VERSION 5.7 ;
BUSBITCHARS "[]" ;
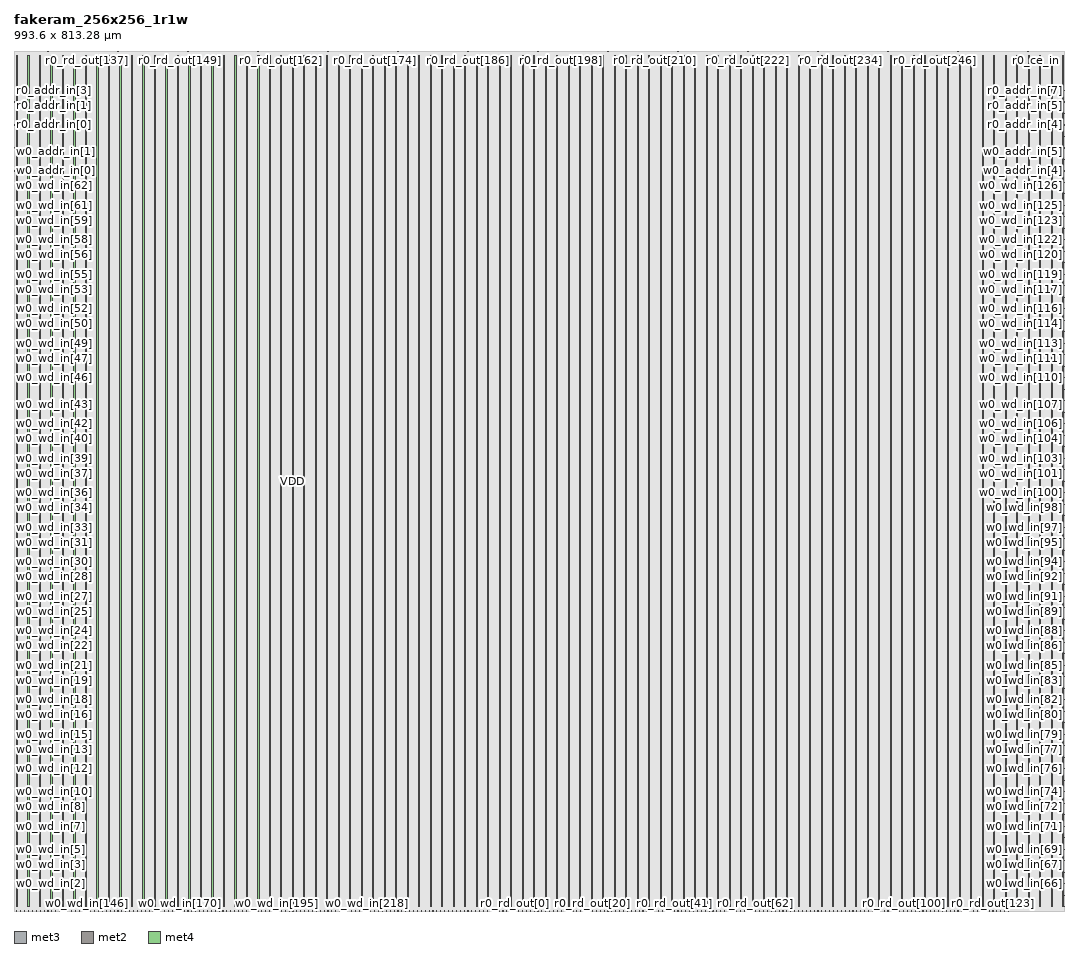
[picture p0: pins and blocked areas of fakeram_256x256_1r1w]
MACRO fakeram_256x256_1r1w
  FOREIGN fakeram_256x256_1r1w 0 0 ;
  SYMMETRY X Y R90 ;
  SIZE 993.600 BY 813.280 ;
  CLASS BLOCK ;
  PIN w0_wd_in[0]
    DIRECTION INPUT ;
    USE SIGNAL ;
    SHAPE ABUTMENT ;
    PORT
      LAYER met3 ;
      RECT 0.000 3.930 0.900 4.230 ;
    END
  END w0_wd_in[0]
  PIN w0_wd_in[1]
    DIRECTION INPUT ;
    USE SIGNAL ;
    SHAPE ABUTMENT ;
    PORT
      LAYER met3 ;
      RECT 0.000 14.810 0.900 15.110 ;
    END
  END w0_wd_in[1]
  PIN w0_wd_in[2]
    DIRECTION INPUT ;
    USE SIGNAL ;
    SHAPE ABUTMENT ;
    PORT
      LAYER met3 ;
      RECT 0.000 25.690 0.900 25.990 ;
    END
  END w0_wd_in[2]
  PIN w0_wd_in[3]
    DIRECTION INPUT ;
    USE SIGNAL ;
    SHAPE ABUTMENT ;
    PORT
      LAYER met3 ;
      RECT 0.000 36.570 0.900 36.870 ;
    END
  END w0_wd_in[3]
  PIN w0_wd_in[4]
    DIRECTION INPUT ;
    USE SIGNAL ;
    SHAPE ABUTMENT ;
    PORT
      LAYER met3 ;
      RECT 0.000 47.450 0.900 47.750 ;
    END
  END w0_wd_in[4]
  PIN w0_wd_in[5]
    DIRECTION INPUT ;
    USE SIGNAL ;
    SHAPE ABUTMENT ;
    PORT
      LAYER met3 ;
      RECT 0.000 58.330 0.900 58.630 ;
    END
  END w0_wd_in[5]
  PIN w0_wd_in[6]
    DIRECTION INPUT ;
    USE SIGNAL ;
    SHAPE ABUTMENT ;
    PORT
      LAYER met3 ;
      RECT 0.000 69.210 0.900 69.510 ;
    END
  END w0_wd_in[6]
  PIN w0_wd_in[7]
    DIRECTION INPUT ;
    USE SIGNAL ;
    SHAPE ABUTMENT ;
    PORT
      LAYER met3 ;
      RECT 0.000 80.090 0.900 80.390 ;
    END
  END w0_wd_in[7]
  PIN w0_wd_in[8]
    DIRECTION INPUT ;
    USE SIGNAL ;
    SHAPE ABUTMENT ;
    PORT
      LAYER met3 ;
      RECT 0.000 90.970 0.900 91.270 ;
    END
  END w0_wd_in[8]
  PIN w0_wd_in[9]
    DIRECTION INPUT ;
    USE SIGNAL ;
    SHAPE ABUTMENT ;
    PORT
      LAYER met3 ;
      RECT 0.000 101.850 0.900 102.150 ;
    END
  END w0_wd_in[9]
  PIN w0_wd_in[10]
    DIRECTION INPUT ;
    USE SIGNAL ;
    SHAPE ABUTMENT ;
    PORT
      LAYER met3 ;
      RECT 0.000 112.730 0.900 113.030 ;
    END
  END w0_wd_in[10]
  PIN w0_wd_in[11]
    DIRECTION INPUT ;
    USE SIGNAL ;
    SHAPE ABUTMENT ;
    PORT
      LAYER met3 ;
      RECT 0.000 123.610 0.900 123.910 ;
    END
  END w0_wd_in[11]
  PIN w0_wd_in[12]
    DIRECTION INPUT ;
    USE SIGNAL ;
    SHAPE ABUTMENT ;
    PORT
      LAYER met3 ;
      RECT 0.000 134.490 0.900 134.790 ;
    END
  END w0_wd_in[12]
  PIN w0_wd_in[13]
    DIRECTION INPUT ;
    USE SIGNAL ;
    SHAPE ABUTMENT ;
    PORT
      LAYER met3 ;
      RECT 0.000 145.370 0.900 145.670 ;
    END
  END w0_wd_in[13]
  PIN w0_wd_in[14]
    DIRECTION INPUT ;
    USE SIGNAL ;
    SHAPE ABUTMENT ;
    PORT
      LAYER met3 ;
      RECT 0.000 156.250 0.900 156.550 ;
    END
  END w0_wd_in[14]
  PIN w0_wd_in[15]
    DIRECTION INPUT ;
    USE SIGNAL ;
    SHAPE ABUTMENT ;
    PORT
      LAYER met3 ;
      RECT 0.000 167.130 0.900 167.430 ;
    END
  END w0_wd_in[15]
  PIN w0_wd_in[16]
    DIRECTION INPUT ;
    USE SIGNAL ;
    SHAPE ABUTMENT ;
    PORT
      LAYER met3 ;
      RECT 0.000 178.010 0.900 178.310 ;
    END
  END w0_wd_in[16]
  PIN w0_wd_in[17]
    DIRECTION INPUT ;
    USE SIGNAL ;
    SHAPE ABUTMENT ;
    PORT
      LAYER met3 ;
      RECT 0.000 188.890 0.900 189.190 ;
    END
  END w0_wd_in[17]
  PIN w0_wd_in[18]
    DIRECTION INPUT ;
    USE SIGNAL ;
    SHAPE ABUTMENT ;
    PORT
      LAYER met3 ;
      RECT 0.000 199.770 0.900 200.070 ;
    END
  END w0_wd_in[18]
  PIN w0_wd_in[19]
    DIRECTION INPUT ;
    USE SIGNAL ;
    SHAPE ABUTMENT ;
    PORT
      LAYER met3 ;
      RECT 0.000 210.650 0.900 210.950 ;
    END
  END w0_wd_in[19]
  PIN w0_wd_in[20]
    DIRECTION INPUT ;
    USE SIGNAL ;
    SHAPE ABUTMENT ;
    PORT
      LAYER met3 ;
      RECT 0.000 221.530 0.900 221.830 ;
    END
  END w0_wd_in[20]
  PIN w0_wd_in[21]
    DIRECTION INPUT ;
    USE SIGNAL ;
    SHAPE ABUTMENT ;
    PORT
      LAYER met3 ;
      RECT 0.000 232.410 0.900 232.710 ;
    END
  END w0_wd_in[21]
  PIN w0_wd_in[22]
    DIRECTION INPUT ;
    USE SIGNAL ;
    SHAPE ABUTMENT ;
    PORT
      LAYER met3 ;
      RECT 0.000 243.290 0.900 243.590 ;
    END
  END w0_wd_in[22]
  PIN w0_wd_in[23]
    DIRECTION INPUT ;
    USE SIGNAL ;
    SHAPE ABUTMENT ;
    PORT
      LAYER met3 ;
      RECT 0.000 254.170 0.900 254.470 ;
    END
  END w0_wd_in[23]
  PIN w0_wd_in[24]
    DIRECTION INPUT ;
    USE SIGNAL ;
    SHAPE ABUTMENT ;
    PORT
      LAYER met3 ;
      RECT 0.000 265.050 0.900 265.350 ;
    END
  END w0_wd_in[24]
  PIN w0_wd_in[25]
    DIRECTION INPUT ;
    USE SIGNAL ;
    SHAPE ABUTMENT ;
    PORT
      LAYER met3 ;
      RECT 0.000 275.930 0.900 276.230 ;
    END
  END w0_wd_in[25]
  PIN w0_wd_in[26]
    DIRECTION INPUT ;
    USE SIGNAL ;
    SHAPE ABUTMENT ;
    PORT
      LAYER met3 ;
      RECT 0.000 286.810 0.900 287.110 ;
    END
  END w0_wd_in[26]
  PIN w0_wd_in[27]
    DIRECTION INPUT ;
    USE SIGNAL ;
    SHAPE ABUTMENT ;
    PORT
      LAYER met3 ;
      RECT 0.000 297.690 0.900 297.990 ;
    END
  END w0_wd_in[27]
  PIN w0_wd_in[28]
    DIRECTION INPUT ;
    USE SIGNAL ;
    SHAPE ABUTMENT ;
    PORT
      LAYER met3 ;
      RECT 0.000 308.570 0.900 308.870 ;
    END
  END w0_wd_in[28]
  PIN w0_wd_in[29]
    DIRECTION INPUT ;
    USE SIGNAL ;
    SHAPE ABUTMENT ;
    PORT
      LAYER met3 ;
      RECT 0.000 319.450 0.900 319.750 ;
    END
  END w0_wd_in[29]
  PIN w0_wd_in[30]
    DIRECTION INPUT ;
    USE SIGNAL ;
    SHAPE ABUTMENT ;
    PORT
      LAYER met3 ;
      RECT 0.000 330.330 0.900 330.630 ;
    END
  END w0_wd_in[30]
  PIN w0_wd_in[31]
    DIRECTION INPUT ;
    USE SIGNAL ;
    SHAPE ABUTMENT ;
    PORT
      LAYER met3 ;
      RECT 0.000 341.210 0.900 341.510 ;
    END
  END w0_wd_in[31]
  PIN w0_wd_in[32]
    DIRECTION INPUT ;
    USE SIGNAL ;
    SHAPE ABUTMENT ;
    PORT
      LAYER met3 ;
      RECT 0.000 352.090 0.900 352.390 ;
    END
  END w0_wd_in[32]
  PIN w0_wd_in[33]
    DIRECTION INPUT ;
    USE SIGNAL ;
    SHAPE ABUTMENT ;
    PORT
      LAYER met3 ;
      RECT 0.000 362.970 0.900 363.270 ;
    END
  END w0_wd_in[33]
  PIN w0_wd_in[34]
    DIRECTION INPUT ;
    USE SIGNAL ;
    SHAPE ABUTMENT ;
    PORT
      LAYER met3 ;
      RECT 0.000 373.850 0.900 374.150 ;
    END
  END w0_wd_in[34]
  PIN w0_wd_in[35]
    DIRECTION INPUT ;
    USE SIGNAL ;
    SHAPE ABUTMENT ;
    PORT
      LAYER met3 ;
      RECT 0.000 384.730 0.900 385.030 ;
    END
  END w0_wd_in[35]
  PIN w0_wd_in[36]
    DIRECTION INPUT ;
    USE SIGNAL ;
    SHAPE ABUTMENT ;
    PORT
      LAYER met3 ;
      RECT 0.000 395.610 0.900 395.910 ;
    END
  END w0_wd_in[36]
  PIN w0_wd_in[37]
    DIRECTION INPUT ;
    USE SIGNAL ;
    SHAPE ABUTMENT ;
    PORT
      LAYER met3 ;
      RECT 0.000 406.490 0.900 406.790 ;
    END
  END w0_wd_in[37]
  PIN w0_wd_in[38]
    DIRECTION INPUT ;
    USE SIGNAL ;
    SHAPE ABUTMENT ;
    PORT
      LAYER met3 ;
      RECT 0.000 417.370 0.900 417.670 ;
    END
  END w0_wd_in[38]
  PIN w0_wd_in[39]
    DIRECTION INPUT ;
    USE SIGNAL ;
    SHAPE ABUTMENT ;
    PORT
      LAYER met3 ;
      RECT 0.000 428.250 0.900 428.550 ;
    END
  END w0_wd_in[39]
  PIN w0_wd_in[40]
    DIRECTION INPUT ;
    USE SIGNAL ;
    SHAPE ABUTMENT ;
    PORT
      LAYER met3 ;
      RECT 0.000 439.130 0.900 439.430 ;
    END
  END w0_wd_in[40]
  PIN w0_wd_in[41]
    DIRECTION INPUT ;
    USE SIGNAL ;
    SHAPE ABUTMENT ;
    PORT
      LAYER met3 ;
      RECT 0.000 450.010 0.900 450.310 ;
    END
  END w0_wd_in[41]
  PIN w0_wd_in[42]
    DIRECTION INPUT ;
    USE SIGNAL ;
    SHAPE ABUTMENT ;
    PORT
      LAYER met3 ;
      RECT 0.000 460.890 0.900 461.190 ;
    END
  END w0_wd_in[42]
  PIN w0_wd_in[43]
    DIRECTION INPUT ;
    USE SIGNAL ;
    SHAPE ABUTMENT ;
    PORT
      LAYER met3 ;
      RECT 0.000 471.770 0.900 472.070 ;
    END
  END w0_wd_in[43]
  PIN w0_wd_in[44]
    DIRECTION INPUT ;
    USE SIGNAL ;
    SHAPE ABUTMENT ;
    PORT
      LAYER met3 ;
      RECT 0.000 482.650 0.900 482.950 ;
    END
  END w0_wd_in[44]
  PIN w0_wd_in[45]
    DIRECTION INPUT ;
    USE SIGNAL ;
    SHAPE ABUTMENT ;
    PORT
      LAYER met3 ;
      RECT 0.000 493.530 0.900 493.830 ;
    END
  END w0_wd_in[45]
  PIN w0_wd_in[46]
    DIRECTION INPUT ;
    USE SIGNAL ;
    SHAPE ABUTMENT ;
    PORT
      LAYER met3 ;
      RECT 0.000 504.410 0.900 504.710 ;
    END
  END w0_wd_in[46]
  PIN w0_wd_in[47]
    DIRECTION INPUT ;
    USE SIGNAL ;
    SHAPE ABUTMENT ;
    PORT
      LAYER met3 ;
      RECT 0.000 515.290 0.900 515.590 ;
    END
  END w0_wd_in[47]
  PIN w0_wd_in[48]
    DIRECTION INPUT ;
    USE SIGNAL ;
    SHAPE ABUTMENT ;
    PORT
      LAYER met3 ;
      RECT 0.000 526.170 0.900 526.470 ;
    END
  END w0_wd_in[48]
  PIN w0_wd_in[49]
    DIRECTION INPUT ;
    USE SIGNAL ;
    SHAPE ABUTMENT ;
    PORT
      LAYER met3 ;
      RECT 0.000 537.050 0.900 537.350 ;
    END
  END w0_wd_in[49]
  PIN w0_wd_in[50]
    DIRECTION INPUT ;
    USE SIGNAL ;
    SHAPE ABUTMENT ;
    PORT
      LAYER met3 ;
      RECT 0.000 547.930 0.900 548.230 ;
    END
  END w0_wd_in[50]
  PIN w0_wd_in[51]
    DIRECTION INPUT ;
    USE SIGNAL ;
    SHAPE ABUTMENT ;
    PORT
      LAYER met3 ;
      RECT 0.000 558.810 0.900 559.110 ;
    END
  END w0_wd_in[51]
  PIN w0_wd_in[52]
    DIRECTION INPUT ;
    USE SIGNAL ;
    SHAPE ABUTMENT ;
    PORT
      LAYER met3 ;
      RECT 0.000 569.690 0.900 569.990 ;
    END
  END w0_wd_in[52]
  PIN w0_wd_in[53]
    DIRECTION INPUT ;
    USE SIGNAL ;
    SHAPE ABUTMENT ;
    PORT
      LAYER met3 ;
      RECT 0.000 580.570 0.900 580.870 ;
    END
  END w0_wd_in[53]
  PIN w0_wd_in[54]
    DIRECTION INPUT ;
    USE SIGNAL ;
    SHAPE ABUTMENT ;
    PORT
      LAYER met3 ;
      RECT 0.000 591.450 0.900 591.750 ;
    END
  END w0_wd_in[54]
  PIN w0_wd_in[55]
    DIRECTION INPUT ;
    USE SIGNAL ;
    SHAPE ABUTMENT ;
    PORT
      LAYER met3 ;
      RECT 0.000 602.330 0.900 602.630 ;
    END
  END w0_wd_in[55]
  PIN w0_wd_in[56]
    DIRECTION INPUT ;
    USE SIGNAL ;
    SHAPE ABUTMENT ;
    PORT
      LAYER met3 ;
      RECT 0.000 613.210 0.900 613.510 ;
    END
  END w0_wd_in[56]
  PIN w0_wd_in[57]
    DIRECTION INPUT ;
    USE SIGNAL ;
    SHAPE ABUTMENT ;
    PORT
      LAYER met3 ;
      RECT 0.000 624.090 0.900 624.390 ;
    END
  END w0_wd_in[57]
  PIN w0_wd_in[58]
    DIRECTION INPUT ;
    USE SIGNAL ;
    SHAPE ABUTMENT ;
    PORT
      LAYER met3 ;
      RECT 0.000 634.970 0.900 635.270 ;
    END
  END w0_wd_in[58]
  PIN w0_wd_in[59]
    DIRECTION INPUT ;
    USE SIGNAL ;
    SHAPE ABUTMENT ;
    PORT
      LAYER met3 ;
      RECT 0.000 645.850 0.900 646.150 ;
    END
  END w0_wd_in[59]
  PIN w0_wd_in[60]
    DIRECTION INPUT ;
    USE SIGNAL ;
    SHAPE ABUTMENT ;
    PORT
      LAYER met3 ;
      RECT 0.000 656.730 0.900 657.030 ;
    END
  END w0_wd_in[60]
  PIN w0_wd_in[61]
    DIRECTION INPUT ;
    USE SIGNAL ;
    SHAPE ABUTMENT ;
    PORT
      LAYER met3 ;
      RECT 0.000 667.610 0.900 667.910 ;
    END
  END w0_wd_in[61]
  PIN w0_wd_in[62]
    DIRECTION INPUT ;
    USE SIGNAL ;
    SHAPE ABUTMENT ;
    PORT
      LAYER met3 ;
      RECT 0.000 678.490 0.900 678.790 ;
    END
  END w0_wd_in[62]
  PIN w0_wd_in[63]
    DIRECTION INPUT ;
    USE SIGNAL ;
    SHAPE ABUTMENT ;
    PORT
      LAYER met3 ;
      RECT 0.000 689.370 0.900 689.670 ;
    END
  END w0_wd_in[63]
  PIN w0_wd_in[64]
    DIRECTION INPUT ;
    USE SIGNAL ;
    SHAPE ABUTMENT ;
    PORT
      LAYER met3 ;
      RECT 992.700 3.930 993.600 4.230 ;
    END
  END w0_wd_in[64]
  PIN w0_wd_in[65]
    DIRECTION INPUT ;
    USE SIGNAL ;
    SHAPE ABUTMENT ;
    PORT
      LAYER met3 ;
      RECT 992.700 14.810 993.600 15.110 ;
    END
  END w0_wd_in[65]
  PIN w0_wd_in[66]
    DIRECTION INPUT ;
    USE SIGNAL ;
    SHAPE ABUTMENT ;
    PORT
      LAYER met3 ;
      RECT 992.700 25.690 993.600 25.990 ;
    END
  END w0_wd_in[66]
  PIN w0_wd_in[67]
    DIRECTION INPUT ;
    USE SIGNAL ;
    SHAPE ABUTMENT ;
    PORT
      LAYER met3 ;
      RECT 992.700 36.570 993.600 36.870 ;
    END
  END w0_wd_in[67]
  PIN w0_wd_in[68]
    DIRECTION INPUT ;
    USE SIGNAL ;
    SHAPE ABUTMENT ;
    PORT
      LAYER met3 ;
      RECT 992.700 47.450 993.600 47.750 ;
    END
  END w0_wd_in[68]
  PIN w0_wd_in[69]
    DIRECTION INPUT ;
    USE SIGNAL ;
    SHAPE ABUTMENT ;
    PORT
      LAYER met3 ;
      RECT 992.700 58.330 993.600 58.630 ;
    END
  END w0_wd_in[69]
  PIN w0_wd_in[70]
    DIRECTION INPUT ;
    USE SIGNAL ;
    SHAPE ABUTMENT ;
    PORT
      LAYER met3 ;
      RECT 992.700 69.210 993.600 69.510 ;
    END
  END w0_wd_in[70]
  PIN w0_wd_in[71]
    DIRECTION INPUT ;
    USE SIGNAL ;
    SHAPE ABUTMENT ;
    PORT
      LAYER met3 ;
      RECT 992.700 80.090 993.600 80.390 ;
    END
  END w0_wd_in[71]
  PIN w0_wd_in[72]
    DIRECTION INPUT ;
    USE SIGNAL ;
    SHAPE ABUTMENT ;
    PORT
      LAYER met3 ;
      RECT 992.700 90.970 993.600 91.270 ;
    END
  END w0_wd_in[72]
  PIN w0_wd_in[73]
    DIRECTION INPUT ;
    USE SIGNAL ;
    SHAPE ABUTMENT ;
    PORT
      LAYER met3 ;
      RECT 992.700 101.850 993.600 102.150 ;
    END
  END w0_wd_in[73]
  PIN w0_wd_in[74]
    DIRECTION INPUT ;
    USE SIGNAL ;
    SHAPE ABUTMENT ;
    PORT
      LAYER met3 ;
      RECT 992.700 112.730 993.600 113.030 ;
    END
  END w0_wd_in[74]
  PIN w0_wd_in[75]
    DIRECTION INPUT ;
    USE SIGNAL ;
    SHAPE ABUTMENT ;
    PORT
      LAYER met3 ;
      RECT 992.700 123.610 993.600 123.910 ;
    END
  END w0_wd_in[75]
  PIN w0_wd_in[76]
    DIRECTION INPUT ;
    USE SIGNAL ;
    SHAPE ABUTMENT ;
    PORT
      LAYER met3 ;
      RECT 992.700 134.490 993.600 134.790 ;
    END
  END w0_wd_in[76]
  PIN w0_wd_in[77]
    DIRECTION INPUT ;
    USE SIGNAL ;
    SHAPE ABUTMENT ;
    PORT
      LAYER met3 ;
      RECT 992.700 145.370 993.600 145.670 ;
    END
  END w0_wd_in[77]
  PIN w0_wd_in[78]
    DIRECTION INPUT ;
    USE SIGNAL ;
    SHAPE ABUTMENT ;
    PORT
      LAYER met3 ;
      RECT 992.700 156.250 993.600 156.550 ;
    END
  END w0_wd_in[78]
  PIN w0_wd_in[79]
    DIRECTION INPUT ;
    USE SIGNAL ;
    SHAPE ABUTMENT ;
    PORT
      LAYER met3 ;
      RECT 992.700 167.130 993.600 167.430 ;
    END
  END w0_wd_in[79]
  PIN w0_wd_in[80]
    DIRECTION INPUT ;
    USE SIGNAL ;
    SHAPE ABUTMENT ;
    PORT
      LAYER met3 ;
      RECT 992.700 178.010 993.600 178.310 ;
    END
  END w0_wd_in[80]
  PIN w0_wd_in[81]
    DIRECTION INPUT ;
    USE SIGNAL ;
    SHAPE ABUTMENT ;
    PORT
      LAYER met3 ;
      RECT 992.700 188.890 993.600 189.190 ;
    END
  END w0_wd_in[81]
  PIN w0_wd_in[82]
    DIRECTION INPUT ;
    USE SIGNAL ;
    SHAPE ABUTMENT ;
    PORT
      LAYER met3 ;
      RECT 992.700 199.770 993.600 200.070 ;
    END
  END w0_wd_in[82]
  PIN w0_wd_in[83]
    DIRECTION INPUT ;
    USE SIGNAL ;
    SHAPE ABUTMENT ;
    PORT
      LAYER met3 ;
      RECT 992.700 210.650 993.600 210.950 ;
    END
  END w0_wd_in[83]
  PIN w0_wd_in[84]
    DIRECTION INPUT ;
    USE SIGNAL ;
    SHAPE ABUTMENT ;
    PORT
      LAYER met3 ;
      RECT 992.700 221.530 993.600 221.830 ;
    END
  END w0_wd_in[84]
  PIN w0_wd_in[85]
    DIRECTION INPUT ;
    USE SIGNAL ;
    SHAPE ABUTMENT ;
    PORT
      LAYER met3 ;
      RECT 992.700 232.410 993.600 232.710 ;
    END
  END w0_wd_in[85]
  PIN w0_wd_in[86]
    DIRECTION INPUT ;
    USE SIGNAL ;
    SHAPE ABUTMENT ;
    PORT
      LAYER met3 ;
      RECT 992.700 243.290 993.600 243.590 ;
    END
  END w0_wd_in[86]
  PIN w0_wd_in[87]
    DIRECTION INPUT ;
    USE SIGNAL ;
    SHAPE ABUTMENT ;
    PORT
      LAYER met3 ;
      RECT 992.700 254.170 993.600 254.470 ;
    END
  END w0_wd_in[87]
  PIN w0_wd_in[88]
    DIRECTION INPUT ;
    USE SIGNAL ;
    SHAPE ABUTMENT ;
    PORT
      LAYER met3 ;
      RECT 992.700 265.050 993.600 265.350 ;
    END
  END w0_wd_in[88]
  PIN w0_wd_in[89]
    DIRECTION INPUT ;
    USE SIGNAL ;
    SHAPE ABUTMENT ;
    PORT
      LAYER met3 ;
      RECT 992.700 275.930 993.600 276.230 ;
    END
  END w0_wd_in[89]
  PIN w0_wd_in[90]
    DIRECTION INPUT ;
    USE SIGNAL ;
    SHAPE ABUTMENT ;
    PORT
      LAYER met3 ;
      RECT 992.700 286.810 993.600 287.110 ;
    END
  END w0_wd_in[90]
  PIN w0_wd_in[91]
    DIRECTION INPUT ;
    USE SIGNAL ;
    SHAPE ABUTMENT ;
    PORT
      LAYER met3 ;
      RECT 992.700 297.690 993.600 297.990 ;
    END
  END w0_wd_in[91]
  PIN w0_wd_in[92]
    DIRECTION INPUT ;
    USE SIGNAL ;
    SHAPE ABUTMENT ;
    PORT
      LAYER met3 ;
      RECT 992.700 308.570 993.600 308.870 ;
    END
  END w0_wd_in[92]
  PIN w0_wd_in[93]
    DIRECTION INPUT ;
    USE SIGNAL ;
    SHAPE ABUTMENT ;
    PORT
      LAYER met3 ;
      RECT 992.700 319.450 993.600 319.750 ;
    END
  END w0_wd_in[93]
  PIN w0_wd_in[94]
    DIRECTION INPUT ;
    USE SIGNAL ;
    SHAPE ABUTMENT ;
    PORT
      LAYER met3 ;
      RECT 992.700 330.330 993.600 330.630 ;
    END
  END w0_wd_in[94]
  PIN w0_wd_in[95]
    DIRECTION INPUT ;
    USE SIGNAL ;
    SHAPE ABUTMENT ;
    PORT
      LAYER met3 ;
      RECT 992.700 341.210 993.600 341.510 ;
    END
  END w0_wd_in[95]
  PIN w0_wd_in[96]
    DIRECTION INPUT ;
    USE SIGNAL ;
    SHAPE ABUTMENT ;
    PORT
      LAYER met3 ;
      RECT 992.700 352.090 993.600 352.390 ;
    END
  END w0_wd_in[96]
  PIN w0_wd_in[97]
    DIRECTION INPUT ;
    USE SIGNAL ;
    SHAPE ABUTMENT ;
    PORT
      LAYER met3 ;
      RECT 992.700 362.970 993.600 363.270 ;
    END
  END w0_wd_in[97]
  PIN w0_wd_in[98]
    DIRECTION INPUT ;
    USE SIGNAL ;
    SHAPE ABUTMENT ;
    PORT
      LAYER met3 ;
      RECT 992.700 373.850 993.600 374.150 ;
    END
  END w0_wd_in[98]
  PIN w0_wd_in[99]
    DIRECTION INPUT ;
    USE SIGNAL ;
    SHAPE ABUTMENT ;
    PORT
      LAYER met3 ;
      RECT 992.700 384.730 993.600 385.030 ;
    END
  END w0_wd_in[99]
  PIN w0_wd_in[100]
    DIRECTION INPUT ;
    USE SIGNAL ;
    SHAPE ABUTMENT ;
    PORT
      LAYER met3 ;
      RECT 992.700 395.610 993.600 395.910 ;
    END
  END w0_wd_in[100]
  PIN w0_wd_in[101]
    DIRECTION INPUT ;
    USE SIGNAL ;
    SHAPE ABUTMENT ;
    PORT
      LAYER met3 ;
      RECT 992.700 406.490 993.600 406.790 ;
    END
  END w0_wd_in[101]
  PIN w0_wd_in[102]
    DIRECTION INPUT ;
    USE SIGNAL ;
    SHAPE ABUTMENT ;
    PORT
      LAYER met3 ;
      RECT 992.700 417.370 993.600 417.670 ;
    END
  END w0_wd_in[102]
  PIN w0_wd_in[103]
    DIRECTION INPUT ;
    USE SIGNAL ;
    SHAPE ABUTMENT ;
    PORT
      LAYER met3 ;
      RECT 992.700 428.250 993.600 428.550 ;
    END
  END w0_wd_in[103]
  PIN w0_wd_in[104]
    DIRECTION INPUT ;
    USE SIGNAL ;
    SHAPE ABUTMENT ;
    PORT
      LAYER met3 ;
      RECT 992.700 439.130 993.600 439.430 ;
    END
  END w0_wd_in[104]
  PIN w0_wd_in[105]
    DIRECTION INPUT ;
    USE SIGNAL ;
    SHAPE ABUTMENT ;
    PORT
      LAYER met3 ;
      RECT 992.700 450.010 993.600 450.310 ;
    END
  END w0_wd_in[105]
  PIN w0_wd_in[106]
    DIRECTION INPUT ;
    USE SIGNAL ;
    SHAPE ABUTMENT ;
    PORT
      LAYER met3 ;
      RECT 992.700 460.890 993.600 461.190 ;
    END
  END w0_wd_in[106]
  PIN w0_wd_in[107]
    DIRECTION INPUT ;
    USE SIGNAL ;
    SHAPE ABUTMENT ;
    PORT
      LAYER met3 ;
      RECT 992.700 471.770 993.600 472.070 ;
    END
  END w0_wd_in[107]
  PIN w0_wd_in[108]
    DIRECTION INPUT ;
    USE SIGNAL ;
    SHAPE ABUTMENT ;
    PORT
      LAYER met3 ;
      RECT 992.700 482.650 993.600 482.950 ;
    END
  END w0_wd_in[108]
  PIN w0_wd_in[109]
    DIRECTION INPUT ;
    USE SIGNAL ;
    SHAPE ABUTMENT ;
    PORT
      LAYER met3 ;
      RECT 992.700 493.530 993.600 493.830 ;
    END
  END w0_wd_in[109]
  PIN w0_wd_in[110]
    DIRECTION INPUT ;
    USE SIGNAL ;
    SHAPE ABUTMENT ;
    PORT
      LAYER met3 ;
      RECT 992.700 504.410 993.600 504.710 ;
    END
  END w0_wd_in[110]
  PIN w0_wd_in[111]
    DIRECTION INPUT ;
    USE SIGNAL ;
    SHAPE ABUTMENT ;
    PORT
      LAYER met3 ;
      RECT 992.700 515.290 993.600 515.590 ;
    END
  END w0_wd_in[111]
  PIN w0_wd_in[112]
    DIRECTION INPUT ;
    USE SIGNAL ;
    SHAPE ABUTMENT ;
    PORT
      LAYER met3 ;
      RECT 992.700 526.170 993.600 526.470 ;
    END
  END w0_wd_in[112]
  PIN w0_wd_in[113]
    DIRECTION INPUT ;
    USE SIGNAL ;
    SHAPE ABUTMENT ;
    PORT
      LAYER met3 ;
      RECT 992.700 537.050 993.600 537.350 ;
    END
  END w0_wd_in[113]
  PIN w0_wd_in[114]
    DIRECTION INPUT ;
    USE SIGNAL ;
    SHAPE ABUTMENT ;
    PORT
      LAYER met3 ;
      RECT 992.700 547.930 993.600 548.230 ;
    END
  END w0_wd_in[114]
  PIN w0_wd_in[115]
    DIRECTION INPUT ;
    USE SIGNAL ;
    SHAPE ABUTMENT ;
    PORT
      LAYER met3 ;
      RECT 992.700 558.810 993.600 559.110 ;
    END
  END w0_wd_in[115]
  PIN w0_wd_in[116]
    DIRECTION INPUT ;
    USE SIGNAL ;
    SHAPE ABUTMENT ;
    PORT
      LAYER met3 ;
      RECT 992.700 569.690 993.600 569.990 ;
    END
  END w0_wd_in[116]
  PIN w0_wd_in[117]
    DIRECTION INPUT ;
    USE SIGNAL ;
    SHAPE ABUTMENT ;
    PORT
      LAYER met3 ;
      RECT 992.700 580.570 993.600 580.870 ;
    END
  END w0_wd_in[117]
  PIN w0_wd_in[118]
    DIRECTION INPUT ;
    USE SIGNAL ;
    SHAPE ABUTMENT ;
    PORT
      LAYER met3 ;
      RECT 992.700 591.450 993.600 591.750 ;
    END
  END w0_wd_in[118]
  PIN w0_wd_in[119]
    DIRECTION INPUT ;
    USE SIGNAL ;
    SHAPE ABUTMENT ;
    PORT
      LAYER met3 ;
      RECT 992.700 602.330 993.600 602.630 ;
    END
  END w0_wd_in[119]
  PIN w0_wd_in[120]
    DIRECTION INPUT ;
    USE SIGNAL ;
    SHAPE ABUTMENT ;
    PORT
      LAYER met3 ;
      RECT 992.700 613.210 993.600 613.510 ;
    END
  END w0_wd_in[120]
  PIN w0_wd_in[121]
    DIRECTION INPUT ;
    USE SIGNAL ;
    SHAPE ABUTMENT ;
    PORT
      LAYER met3 ;
      RECT 992.700 624.090 993.600 624.390 ;
    END
  END w0_wd_in[121]
  PIN w0_wd_in[122]
    DIRECTION INPUT ;
    USE SIGNAL ;
    SHAPE ABUTMENT ;
    PORT
      LAYER met3 ;
      RECT 992.700 634.970 993.600 635.270 ;
    END
  END w0_wd_in[122]
  PIN w0_wd_in[123]
    DIRECTION INPUT ;
    USE SIGNAL ;
    SHAPE ABUTMENT ;
    PORT
      LAYER met3 ;
      RECT 992.700 645.850 993.600 646.150 ;
    END
  END w0_wd_in[123]
  PIN w0_wd_in[124]
    DIRECTION INPUT ;
    USE SIGNAL ;
    SHAPE ABUTMENT ;
    PORT
      LAYER met3 ;
      RECT 992.700 656.730 993.600 657.030 ;
    END
  END w0_wd_in[124]
  PIN w0_wd_in[125]
    DIRECTION INPUT ;
    USE SIGNAL ;
    SHAPE ABUTMENT ;
    PORT
      LAYER met3 ;
      RECT 992.700 667.610 993.600 667.910 ;
    END
  END w0_wd_in[125]
  PIN w0_wd_in[126]
    DIRECTION INPUT ;
    USE SIGNAL ;
    SHAPE ABUTMENT ;
    PORT
      LAYER met3 ;
      RECT 992.700 678.490 993.600 678.790 ;
    END
  END w0_wd_in[126]
  PIN w0_wd_in[127]
    DIRECTION INPUT ;
    USE SIGNAL ;
    SHAPE ABUTMENT ;
    PORT
      LAYER met3 ;
      RECT 992.700 689.370 993.600 689.670 ;
    END
  END w0_wd_in[127]
  PIN w0_wd_in[128]
    DIRECTION OUTPUT ;
    USE SIGNAL ;
    SHAPE ABUTMENT ;
    PORT
      LAYER met2 ;
      RECT 2.690 0.000 2.830 0.420 ;
    END
  END w0_wd_in[128]
  PIN w0_wd_in[129]
    DIRECTION OUTPUT ;
    USE SIGNAL ;
    SHAPE ABUTMENT ;
    PORT
      LAYER met2 ;
      RECT 6.370 0.000 6.510 0.420 ;
    END
  END w0_wd_in[129]
  PIN w0_wd_in[130]
    DIRECTION OUTPUT ;
    USE SIGNAL ;
    SHAPE ABUTMENT ;
    PORT
      LAYER met2 ;
      RECT 10.050 0.000 10.190 0.420 ;
    END
  END w0_wd_in[130]
  PIN w0_wd_in[131]
    DIRECTION OUTPUT ;
    USE SIGNAL ;
    SHAPE ABUTMENT ;
    PORT
      LAYER met2 ;
      RECT 13.730 0.000 13.870 0.420 ;
    END
  END w0_wd_in[131]
  PIN w0_wd_in[132]
    DIRECTION OUTPUT ;
    USE SIGNAL ;
    SHAPE ABUTMENT ;
    PORT
      LAYER met2 ;
      RECT 17.410 0.000 17.550 0.420 ;
    END
  END w0_wd_in[132]
  PIN w0_wd_in[133]
    DIRECTION OUTPUT ;
    USE SIGNAL ;
    SHAPE ABUTMENT ;
    PORT
      LAYER met2 ;
      RECT 21.090 0.000 21.230 0.420 ;
    END
  END w0_wd_in[133]
  PIN w0_wd_in[134]
    DIRECTION OUTPUT ;
    USE SIGNAL ;
    SHAPE ABUTMENT ;
    PORT
      LAYER met2 ;
      RECT 24.770 0.000 24.910 0.420 ;
    END
  END w0_wd_in[134]
  PIN w0_wd_in[135]
    DIRECTION OUTPUT ;
    USE SIGNAL ;
    SHAPE ABUTMENT ;
    PORT
      LAYER met2 ;
      RECT 28.450 0.000 28.590 0.420 ;
    END
  END w0_wd_in[135]
  PIN w0_wd_in[136]
    DIRECTION OUTPUT ;
    USE SIGNAL ;
    SHAPE ABUTMENT ;
    PORT
      LAYER met2 ;
      RECT 32.130 0.000 32.270 0.420 ;
    END
  END w0_wd_in[136]
  PIN w0_wd_in[137]
    DIRECTION OUTPUT ;
    USE SIGNAL ;
    SHAPE ABUTMENT ;
    PORT
      LAYER met2 ;
      RECT 35.810 0.000 35.950 0.420 ;
    END
  END w0_wd_in[137]
  PIN w0_wd_in[138]
    DIRECTION OUTPUT ;
    USE SIGNAL ;
    SHAPE ABUTMENT ;
    PORT
      LAYER met2 ;
      RECT 39.490 0.000 39.630 0.420 ;
    END
  END w0_wd_in[138]
  PIN w0_wd_in[139]
    DIRECTION OUTPUT ;
    USE SIGNAL ;
    SHAPE ABUTMENT ;
    PORT
      LAYER met2 ;
      RECT 43.170 0.000 43.310 0.420 ;
    END
  END w0_wd_in[139]
  PIN w0_wd_in[140]
    DIRECTION OUTPUT ;
    USE SIGNAL ;
    SHAPE ABUTMENT ;
    PORT
      LAYER met2 ;
      RECT 46.850 0.000 46.990 0.420 ;
    END
  END w0_wd_in[140]
  PIN w0_wd_in[141]
    DIRECTION OUTPUT ;
    USE SIGNAL ;
    SHAPE ABUTMENT ;
    PORT
      LAYER met2 ;
      RECT 50.530 0.000 50.670 0.420 ;
    END
  END w0_wd_in[141]
  PIN w0_wd_in[142]
    DIRECTION OUTPUT ;
    USE SIGNAL ;
    SHAPE ABUTMENT ;
    PORT
      LAYER met2 ;
      RECT 54.210 0.000 54.350 0.420 ;
    END
  END w0_wd_in[142]
  PIN w0_wd_in[143]
    DIRECTION OUTPUT ;
    USE SIGNAL ;
    SHAPE ABUTMENT ;
    PORT
      LAYER met2 ;
      RECT 57.890 0.000 58.030 0.420 ;
    END
  END w0_wd_in[143]
  PIN w0_wd_in[144]
    DIRECTION OUTPUT ;
    USE SIGNAL ;
    SHAPE ABUTMENT ;
    PORT
      LAYER met2 ;
      RECT 61.570 0.000 61.710 0.420 ;
    END
  END w0_wd_in[144]
  PIN w0_wd_in[145]
    DIRECTION OUTPUT ;
    USE SIGNAL ;
    SHAPE ABUTMENT ;
    PORT
      LAYER met2 ;
      RECT 65.250 0.000 65.390 0.420 ;
    END
  END w0_wd_in[145]
  PIN w0_wd_in[146]
    DIRECTION OUTPUT ;
    USE SIGNAL ;
    SHAPE ABUTMENT ;
    PORT
      LAYER met2 ;
      RECT 68.930 0.000 69.070 0.420 ;
    END
  END w0_wd_in[146]
  PIN w0_wd_in[147]
    DIRECTION OUTPUT ;
    USE SIGNAL ;
    SHAPE ABUTMENT ;
    PORT
      LAYER met2 ;
      RECT 72.610 0.000 72.750 0.420 ;
    END
  END w0_wd_in[147]
  PIN w0_wd_in[148]
    DIRECTION OUTPUT ;
    USE SIGNAL ;
    SHAPE ABUTMENT ;
    PORT
      LAYER met2 ;
      RECT 76.290 0.000 76.430 0.420 ;
    END
  END w0_wd_in[148]
  PIN w0_wd_in[149]
    DIRECTION OUTPUT ;
    USE SIGNAL ;
    SHAPE ABUTMENT ;
    PORT
      LAYER met2 ;
      RECT 79.970 0.000 80.110 0.420 ;
    END
  END w0_wd_in[149]
  PIN w0_wd_in[150]
    DIRECTION OUTPUT ;
    USE SIGNAL ;
    SHAPE ABUTMENT ;
    PORT
      LAYER met2 ;
      RECT 83.650 0.000 83.790 0.420 ;
    END
  END w0_wd_in[150]
  PIN w0_wd_in[151]
    DIRECTION OUTPUT ;
    USE SIGNAL ;
    SHAPE ABUTMENT ;
    PORT
      LAYER met2 ;
      RECT 87.330 0.000 87.470 0.420 ;
    END
  END w0_wd_in[151]
  PIN w0_wd_in[152]
    DIRECTION OUTPUT ;
    USE SIGNAL ;
    SHAPE ABUTMENT ;
    PORT
      LAYER met2 ;
      RECT 91.010 0.000 91.150 0.420 ;
    END
  END w0_wd_in[152]
  PIN w0_wd_in[153]
    DIRECTION OUTPUT ;
    USE SIGNAL ;
    SHAPE ABUTMENT ;
    PORT
      LAYER met2 ;
      RECT 94.690 0.000 94.830 0.420 ;
    END
  END w0_wd_in[153]
  PIN w0_wd_in[154]
    DIRECTION OUTPUT ;
    USE SIGNAL ;
    SHAPE ABUTMENT ;
    PORT
      LAYER met2 ;
      RECT 98.370 0.000 98.510 0.420 ;
    END
  END w0_wd_in[154]
  PIN w0_wd_in[155]
    DIRECTION OUTPUT ;
    USE SIGNAL ;
    SHAPE ABUTMENT ;
    PORT
      LAYER met2 ;
      RECT 102.050 0.000 102.190 0.420 ;
    END
  END w0_wd_in[155]
  PIN w0_wd_in[156]
    DIRECTION OUTPUT ;
    USE SIGNAL ;
    SHAPE ABUTMENT ;
    PORT
      LAYER met2 ;
      RECT 105.730 0.000 105.870 0.420 ;
    END
  END w0_wd_in[156]
  PIN w0_wd_in[157]
    DIRECTION OUTPUT ;
    USE SIGNAL ;
    SHAPE ABUTMENT ;
    PORT
      LAYER met2 ;
      RECT 109.410 0.000 109.550 0.420 ;
    END
  END w0_wd_in[157]
  PIN w0_wd_in[158]
    DIRECTION OUTPUT ;
    USE SIGNAL ;
    SHAPE ABUTMENT ;
    PORT
      LAYER met2 ;
      RECT 113.090 0.000 113.230 0.420 ;
    END
  END w0_wd_in[158]
  PIN w0_wd_in[159]
    DIRECTION OUTPUT ;
    USE SIGNAL ;
    SHAPE ABUTMENT ;
    PORT
      LAYER met2 ;
      RECT 116.770 0.000 116.910 0.420 ;
    END
  END w0_wd_in[159]
  PIN w0_wd_in[160]
    DIRECTION OUTPUT ;
    USE SIGNAL ;
    SHAPE ABUTMENT ;
    PORT
      LAYER met2 ;
      RECT 120.450 0.000 120.590 0.420 ;
    END
  END w0_wd_in[160]
  PIN w0_wd_in[161]
    DIRECTION OUTPUT ;
    USE SIGNAL ;
    SHAPE ABUTMENT ;
    PORT
      LAYER met2 ;
      RECT 124.130 0.000 124.270 0.420 ;
    END
  END w0_wd_in[161]
  PIN w0_wd_in[162]
    DIRECTION OUTPUT ;
    USE SIGNAL ;
    SHAPE ABUTMENT ;
    PORT
      LAYER met2 ;
      RECT 127.810 0.000 127.950 0.420 ;
    END
  END w0_wd_in[162]
  PIN w0_wd_in[163]
    DIRECTION OUTPUT ;
    USE SIGNAL ;
    SHAPE ABUTMENT ;
    PORT
      LAYER met2 ;
      RECT 131.490 0.000 131.630 0.420 ;
    END
  END w0_wd_in[163]
  PIN w0_wd_in[164]
    DIRECTION OUTPUT ;
    USE SIGNAL ;
    SHAPE ABUTMENT ;
    PORT
      LAYER met2 ;
      RECT 135.170 0.000 135.310 0.420 ;
    END
  END w0_wd_in[164]
  PIN w0_wd_in[165]
    DIRECTION OUTPUT ;
    USE SIGNAL ;
    SHAPE ABUTMENT ;
    PORT
      LAYER met2 ;
      RECT 138.850 0.000 138.990 0.420 ;
    END
  END w0_wd_in[165]
  PIN w0_wd_in[166]
    DIRECTION OUTPUT ;
    USE SIGNAL ;
    SHAPE ABUTMENT ;
    PORT
      LAYER met2 ;
      RECT 142.530 0.000 142.670 0.420 ;
    END
  END w0_wd_in[166]
  PIN w0_wd_in[167]
    DIRECTION OUTPUT ;
    USE SIGNAL ;
    SHAPE ABUTMENT ;
    PORT
      LAYER met2 ;
      RECT 146.210 0.000 146.350 0.420 ;
    END
  END w0_wd_in[167]
  PIN w0_wd_in[168]
    DIRECTION OUTPUT ;
    USE SIGNAL ;
    SHAPE ABUTMENT ;
    PORT
      LAYER met2 ;
      RECT 149.890 0.000 150.030 0.420 ;
    END
  END w0_wd_in[168]
  PIN w0_wd_in[169]
    DIRECTION OUTPUT ;
    USE SIGNAL ;
    SHAPE ABUTMENT ;
    PORT
      LAYER met2 ;
      RECT 153.570 0.000 153.710 0.420 ;
    END
  END w0_wd_in[169]
  PIN w0_wd_in[170]
    DIRECTION OUTPUT ;
    USE SIGNAL ;
    SHAPE ABUTMENT ;
    PORT
      LAYER met2 ;
      RECT 157.250 0.000 157.390 0.420 ;
    END
  END w0_wd_in[170]
  PIN w0_wd_in[171]
    DIRECTION OUTPUT ;
    USE SIGNAL ;
    SHAPE ABUTMENT ;
    PORT
      LAYER met2 ;
      RECT 160.930 0.000 161.070 0.420 ;
    END
  END w0_wd_in[171]
  PIN w0_wd_in[172]
    DIRECTION OUTPUT ;
    USE SIGNAL ;
    SHAPE ABUTMENT ;
    PORT
      LAYER met2 ;
      RECT 164.610 0.000 164.750 0.420 ;
    END
  END w0_wd_in[172]
  PIN w0_wd_in[173]
    DIRECTION OUTPUT ;
    USE SIGNAL ;
    SHAPE ABUTMENT ;
    PORT
      LAYER met2 ;
      RECT 168.290 0.000 168.430 0.420 ;
    END
  END w0_wd_in[173]
  PIN w0_wd_in[174]
    DIRECTION OUTPUT ;
    USE SIGNAL ;
    SHAPE ABUTMENT ;
    PORT
      LAYER met2 ;
      RECT 171.970 0.000 172.110 0.420 ;
    END
  END w0_wd_in[174]
  PIN w0_wd_in[175]
    DIRECTION OUTPUT ;
    USE SIGNAL ;
    SHAPE ABUTMENT ;
    PORT
      LAYER met2 ;
      RECT 175.650 0.000 175.790 0.420 ;
    END
  END w0_wd_in[175]
  PIN w0_wd_in[176]
    DIRECTION OUTPUT ;
    USE SIGNAL ;
    SHAPE ABUTMENT ;
    PORT
      LAYER met2 ;
      RECT 179.330 0.000 179.470 0.420 ;
    END
  END w0_wd_in[176]
  PIN w0_wd_in[177]
    DIRECTION OUTPUT ;
    USE SIGNAL ;
    SHAPE ABUTMENT ;
    PORT
      LAYER met2 ;
      RECT 183.010 0.000 183.150 0.420 ;
    END
  END w0_wd_in[177]
  PIN w0_wd_in[178]
    DIRECTION OUTPUT ;
    USE SIGNAL ;
    SHAPE ABUTMENT ;
    PORT
      LAYER met2 ;
      RECT 186.690 0.000 186.830 0.420 ;
    END
  END w0_wd_in[178]
  PIN w0_wd_in[179]
    DIRECTION OUTPUT ;
    USE SIGNAL ;
    SHAPE ABUTMENT ;
    PORT
      LAYER met2 ;
      RECT 190.370 0.000 190.510 0.420 ;
    END
  END w0_wd_in[179]
  PIN w0_wd_in[180]
    DIRECTION OUTPUT ;
    USE SIGNAL ;
    SHAPE ABUTMENT ;
    PORT
      LAYER met2 ;
      RECT 194.050 0.000 194.190 0.420 ;
    END
  END w0_wd_in[180]
  PIN w0_wd_in[181]
    DIRECTION OUTPUT ;
    USE SIGNAL ;
    SHAPE ABUTMENT ;
    PORT
      LAYER met2 ;
      RECT 197.730 0.000 197.870 0.420 ;
    END
  END w0_wd_in[181]
  PIN w0_wd_in[182]
    DIRECTION OUTPUT ;
    USE SIGNAL ;
    SHAPE ABUTMENT ;
    PORT
      LAYER met2 ;
      RECT 201.410 0.000 201.550 0.420 ;
    END
  END w0_wd_in[182]
  PIN w0_wd_in[183]
    DIRECTION OUTPUT ;
    USE SIGNAL ;
    SHAPE ABUTMENT ;
    PORT
      LAYER met2 ;
      RECT 205.090 0.000 205.230 0.420 ;
    END
  END w0_wd_in[183]
  PIN w0_wd_in[184]
    DIRECTION OUTPUT ;
    USE SIGNAL ;
    SHAPE ABUTMENT ;
    PORT
      LAYER met2 ;
      RECT 208.770 0.000 208.910 0.420 ;
    END
  END w0_wd_in[184]
  PIN w0_wd_in[185]
    DIRECTION OUTPUT ;
    USE SIGNAL ;
    SHAPE ABUTMENT ;
    PORT
      LAYER met2 ;
      RECT 212.450 0.000 212.590 0.420 ;
    END
  END w0_wd_in[185]
  PIN w0_wd_in[186]
    DIRECTION OUTPUT ;
    USE SIGNAL ;
    SHAPE ABUTMENT ;
    PORT
      LAYER met2 ;
      RECT 216.130 0.000 216.270 0.420 ;
    END
  END w0_wd_in[186]
  PIN w0_wd_in[187]
    DIRECTION OUTPUT ;
    USE SIGNAL ;
    SHAPE ABUTMENT ;
    PORT
      LAYER met2 ;
      RECT 219.810 0.000 219.950 0.420 ;
    END
  END w0_wd_in[187]
  PIN w0_wd_in[188]
    DIRECTION OUTPUT ;
    USE SIGNAL ;
    SHAPE ABUTMENT ;
    PORT
      LAYER met2 ;
      RECT 223.490 0.000 223.630 0.420 ;
    END
  END w0_wd_in[188]
  PIN w0_wd_in[189]
    DIRECTION OUTPUT ;
    USE SIGNAL ;
    SHAPE ABUTMENT ;
    PORT
      LAYER met2 ;
      RECT 227.170 0.000 227.310 0.420 ;
    END
  END w0_wd_in[189]
  PIN w0_wd_in[190]
    DIRECTION OUTPUT ;
    USE SIGNAL ;
    SHAPE ABUTMENT ;
    PORT
      LAYER met2 ;
      RECT 230.850 0.000 230.990 0.420 ;
    END
  END w0_wd_in[190]
  PIN w0_wd_in[191]
    DIRECTION OUTPUT ;
    USE SIGNAL ;
    SHAPE ABUTMENT ;
    PORT
      LAYER met2 ;
      RECT 234.530 0.000 234.670 0.420 ;
    END
  END w0_wd_in[191]
  PIN w0_wd_in[192]
    DIRECTION OUTPUT ;
    USE SIGNAL ;
    SHAPE ABUTMENT ;
    PORT
      LAYER met2 ;
      RECT 238.210 0.000 238.350 0.420 ;
    END
  END w0_wd_in[192]
  PIN w0_wd_in[193]
    DIRECTION OUTPUT ;
    USE SIGNAL ;
    SHAPE ABUTMENT ;
    PORT
      LAYER met2 ;
      RECT 241.890 0.000 242.030 0.420 ;
    END
  END w0_wd_in[193]
  PIN w0_wd_in[194]
    DIRECTION OUTPUT ;
    USE SIGNAL ;
    SHAPE ABUTMENT ;
    PORT
      LAYER met2 ;
      RECT 245.570 0.000 245.710 0.420 ;
    END
  END w0_wd_in[194]
  PIN w0_wd_in[195]
    DIRECTION OUTPUT ;
    USE SIGNAL ;
    SHAPE ABUTMENT ;
    PORT
      LAYER met2 ;
      RECT 249.250 0.000 249.390 0.420 ;
    END
  END w0_wd_in[195]
  PIN w0_wd_in[196]
    DIRECTION OUTPUT ;
    USE SIGNAL ;
    SHAPE ABUTMENT ;
    PORT
      LAYER met2 ;
      RECT 252.930 0.000 253.070 0.420 ;
    END
  END w0_wd_in[196]
  PIN w0_wd_in[197]
    DIRECTION OUTPUT ;
    USE SIGNAL ;
    SHAPE ABUTMENT ;
    PORT
      LAYER met2 ;
      RECT 256.610 0.000 256.750 0.420 ;
    END
  END w0_wd_in[197]
  PIN w0_wd_in[198]
    DIRECTION OUTPUT ;
    USE SIGNAL ;
    SHAPE ABUTMENT ;
    PORT
      LAYER met2 ;
      RECT 260.290 0.000 260.430 0.420 ;
    END
  END w0_wd_in[198]
  PIN w0_wd_in[199]
    DIRECTION OUTPUT ;
    USE SIGNAL ;
    SHAPE ABUTMENT ;
    PORT
      LAYER met2 ;
      RECT 263.970 0.000 264.110 0.420 ;
    END
  END w0_wd_in[199]
  PIN w0_wd_in[200]
    DIRECTION OUTPUT ;
    USE SIGNAL ;
    SHAPE ABUTMENT ;
    PORT
      LAYER met2 ;
      RECT 267.650 0.000 267.790 0.420 ;
    END
  END w0_wd_in[200]
  PIN w0_wd_in[201]
    DIRECTION OUTPUT ;
    USE SIGNAL ;
    SHAPE ABUTMENT ;
    PORT
      LAYER met2 ;
      RECT 271.330 0.000 271.470 0.420 ;
    END
  END w0_wd_in[201]
  PIN w0_wd_in[202]
    DIRECTION OUTPUT ;
    USE SIGNAL ;
    SHAPE ABUTMENT ;
    PORT
      LAYER met2 ;
      RECT 275.010 0.000 275.150 0.420 ;
    END
  END w0_wd_in[202]
  PIN w0_wd_in[203]
    DIRECTION OUTPUT ;
    USE SIGNAL ;
    SHAPE ABUTMENT ;
    PORT
      LAYER met2 ;
      RECT 278.690 0.000 278.830 0.420 ;
    END
  END w0_wd_in[203]
  PIN w0_wd_in[204]
    DIRECTION OUTPUT ;
    USE SIGNAL ;
    SHAPE ABUTMENT ;
    PORT
      LAYER met2 ;
      RECT 282.370 0.000 282.510 0.420 ;
    END
  END w0_wd_in[204]
  PIN w0_wd_in[205]
    DIRECTION OUTPUT ;
    USE SIGNAL ;
    SHAPE ABUTMENT ;
    PORT
      LAYER met2 ;
      RECT 286.050 0.000 286.190 0.420 ;
    END
  END w0_wd_in[205]
  PIN w0_wd_in[206]
    DIRECTION OUTPUT ;
    USE SIGNAL ;
    SHAPE ABUTMENT ;
    PORT
      LAYER met2 ;
      RECT 289.730 0.000 289.870 0.420 ;
    END
  END w0_wd_in[206]
  PIN w0_wd_in[207]
    DIRECTION OUTPUT ;
    USE SIGNAL ;
    SHAPE ABUTMENT ;
    PORT
      LAYER met2 ;
      RECT 293.410 0.000 293.550 0.420 ;
    END
  END w0_wd_in[207]
  PIN w0_wd_in[208]
    DIRECTION OUTPUT ;
    USE SIGNAL ;
    SHAPE ABUTMENT ;
    PORT
      LAYER met2 ;
      RECT 297.090 0.000 297.230 0.420 ;
    END
  END w0_wd_in[208]
  PIN w0_wd_in[209]
    DIRECTION OUTPUT ;
    USE SIGNAL ;
    SHAPE ABUTMENT ;
    PORT
      LAYER met2 ;
      RECT 300.770 0.000 300.910 0.420 ;
    END
  END w0_wd_in[209]
  PIN w0_wd_in[210]
    DIRECTION OUTPUT ;
    USE SIGNAL ;
    SHAPE ABUTMENT ;
    PORT
      LAYER met2 ;
      RECT 304.450 0.000 304.590 0.420 ;
    END
  END w0_wd_in[210]
  PIN w0_wd_in[211]
    DIRECTION OUTPUT ;
    USE SIGNAL ;
    SHAPE ABUTMENT ;
    PORT
      LAYER met2 ;
      RECT 308.130 0.000 308.270 0.420 ;
    END
  END w0_wd_in[211]
  PIN w0_wd_in[212]
    DIRECTION OUTPUT ;
    USE SIGNAL ;
    SHAPE ABUTMENT ;
    PORT
      LAYER met2 ;
      RECT 311.810 0.000 311.950 0.420 ;
    END
  END w0_wd_in[212]
  PIN w0_wd_in[213]
    DIRECTION OUTPUT ;
    USE SIGNAL ;
    SHAPE ABUTMENT ;
    PORT
      LAYER met2 ;
      RECT 315.490 0.000 315.630 0.420 ;
    END
  END w0_wd_in[213]
  PIN w0_wd_in[214]
    DIRECTION OUTPUT ;
    USE SIGNAL ;
    SHAPE ABUTMENT ;
    PORT
      LAYER met2 ;
      RECT 319.170 0.000 319.310 0.420 ;
    END
  END w0_wd_in[214]
  PIN w0_wd_in[215]
    DIRECTION OUTPUT ;
    USE SIGNAL ;
    SHAPE ABUTMENT ;
    PORT
      LAYER met2 ;
      RECT 322.850 0.000 322.990 0.420 ;
    END
  END w0_wd_in[215]
  PIN w0_wd_in[216]
    DIRECTION OUTPUT ;
    USE SIGNAL ;
    SHAPE ABUTMENT ;
    PORT
      LAYER met2 ;
      RECT 326.530 0.000 326.670 0.420 ;
    END
  END w0_wd_in[216]
  PIN w0_wd_in[217]
    DIRECTION OUTPUT ;
    USE SIGNAL ;
    SHAPE ABUTMENT ;
    PORT
      LAYER met2 ;
      RECT 330.210 0.000 330.350 0.420 ;
    END
  END w0_wd_in[217]
  PIN w0_wd_in[218]
    DIRECTION OUTPUT ;
    USE SIGNAL ;
    SHAPE ABUTMENT ;
    PORT
      LAYER met2 ;
      RECT 333.890 0.000 334.030 0.420 ;
    END
  END w0_wd_in[218]
  PIN w0_wd_in[219]
    DIRECTION OUTPUT ;
    USE SIGNAL ;
    SHAPE ABUTMENT ;
    PORT
      LAYER met2 ;
      RECT 337.570 0.000 337.710 0.420 ;
    END
  END w0_wd_in[219]
  PIN w0_wd_in[220]
    DIRECTION OUTPUT ;
    USE SIGNAL ;
    SHAPE ABUTMENT ;
    PORT
      LAYER met2 ;
      RECT 341.250 0.000 341.390 0.420 ;
    END
  END w0_wd_in[220]
  PIN w0_wd_in[221]
    DIRECTION OUTPUT ;
    USE SIGNAL ;
    SHAPE ABUTMENT ;
    PORT
      LAYER met2 ;
      RECT 344.930 0.000 345.070 0.420 ;
    END
  END w0_wd_in[221]
  PIN w0_wd_in[222]
    DIRECTION OUTPUT ;
    USE SIGNAL ;
    SHAPE ABUTMENT ;
    PORT
      LAYER met2 ;
      RECT 348.610 0.000 348.750 0.420 ;
    END
  END w0_wd_in[222]
  PIN w0_wd_in[223]
    DIRECTION OUTPUT ;
    USE SIGNAL ;
    SHAPE ABUTMENT ;
    PORT
      LAYER met2 ;
      RECT 352.290 0.000 352.430 0.420 ;
    END
  END w0_wd_in[223]
  PIN w0_wd_in[224]
    DIRECTION OUTPUT ;
    USE SIGNAL ;
    SHAPE ABUTMENT ;
    PORT
      LAYER met2 ;
      RECT 355.970 0.000 356.110 0.420 ;
    END
  END w0_wd_in[224]
  PIN w0_wd_in[225]
    DIRECTION OUTPUT ;
    USE SIGNAL ;
    SHAPE ABUTMENT ;
    PORT
      LAYER met2 ;
      RECT 359.650 0.000 359.790 0.420 ;
    END
  END w0_wd_in[225]
  PIN w0_wd_in[226]
    DIRECTION OUTPUT ;
    USE SIGNAL ;
    SHAPE ABUTMENT ;
    PORT
      LAYER met2 ;
      RECT 363.330 0.000 363.470 0.420 ;
    END
  END w0_wd_in[226]
  PIN w0_wd_in[227]
    DIRECTION OUTPUT ;
    USE SIGNAL ;
    SHAPE ABUTMENT ;
    PORT
      LAYER met2 ;
      RECT 367.010 0.000 367.150 0.420 ;
    END
  END w0_wd_in[227]
  PIN w0_wd_in[228]
    DIRECTION OUTPUT ;
    USE SIGNAL ;
    SHAPE ABUTMENT ;
    PORT
      LAYER met2 ;
      RECT 370.690 0.000 370.830 0.420 ;
    END
  END w0_wd_in[228]
  PIN w0_wd_in[229]
    DIRECTION OUTPUT ;
    USE SIGNAL ;
    SHAPE ABUTMENT ;
    PORT
      LAYER met2 ;
      RECT 374.370 0.000 374.510 0.420 ;
    END
  END w0_wd_in[229]
  PIN w0_wd_in[230]
    DIRECTION OUTPUT ;
    USE SIGNAL ;
    SHAPE ABUTMENT ;
    PORT
      LAYER met2 ;
      RECT 378.050 0.000 378.190 0.420 ;
    END
  END w0_wd_in[230]
  PIN w0_wd_in[231]
    DIRECTION OUTPUT ;
    USE SIGNAL ;
    SHAPE ABUTMENT ;
    PORT
      LAYER met2 ;
      RECT 381.730 0.000 381.870 0.420 ;
    END
  END w0_wd_in[231]
  PIN w0_wd_in[232]
    DIRECTION OUTPUT ;
    USE SIGNAL ;
    SHAPE ABUTMENT ;
    PORT
      LAYER met2 ;
      RECT 385.410 0.000 385.550 0.420 ;
    END
  END w0_wd_in[232]
  PIN w0_wd_in[233]
    DIRECTION OUTPUT ;
    USE SIGNAL ;
    SHAPE ABUTMENT ;
    PORT
      LAYER met2 ;
      RECT 389.090 0.000 389.230 0.420 ;
    END
  END w0_wd_in[233]
  PIN w0_wd_in[234]
    DIRECTION OUTPUT ;
    USE SIGNAL ;
    SHAPE ABUTMENT ;
    PORT
      LAYER met2 ;
      RECT 392.770 0.000 392.910 0.420 ;
    END
  END w0_wd_in[234]
  PIN w0_wd_in[235]
    DIRECTION OUTPUT ;
    USE SIGNAL ;
    SHAPE ABUTMENT ;
    PORT
      LAYER met2 ;
      RECT 396.450 0.000 396.590 0.420 ;
    END
  END w0_wd_in[235]
  PIN w0_wd_in[236]
    DIRECTION OUTPUT ;
    USE SIGNAL ;
    SHAPE ABUTMENT ;
    PORT
      LAYER met2 ;
      RECT 400.130 0.000 400.270 0.420 ;
    END
  END w0_wd_in[236]
  PIN w0_wd_in[237]
    DIRECTION OUTPUT ;
    USE SIGNAL ;
    SHAPE ABUTMENT ;
    PORT
      LAYER met2 ;
      RECT 403.810 0.000 403.950 0.420 ;
    END
  END w0_wd_in[237]
  PIN w0_wd_in[238]
    DIRECTION OUTPUT ;
    USE SIGNAL ;
    SHAPE ABUTMENT ;
    PORT
      LAYER met2 ;
      RECT 407.490 0.000 407.630 0.420 ;
    END
  END w0_wd_in[238]
  PIN w0_wd_in[239]
    DIRECTION OUTPUT ;
    USE SIGNAL ;
    SHAPE ABUTMENT ;
    PORT
      LAYER met2 ;
      RECT 411.170 0.000 411.310 0.420 ;
    END
  END w0_wd_in[239]
  PIN w0_wd_in[240]
    DIRECTION OUTPUT ;
    USE SIGNAL ;
    SHAPE ABUTMENT ;
    PORT
      LAYER met2 ;
      RECT 414.850 0.000 414.990 0.420 ;
    END
  END w0_wd_in[240]
  PIN w0_wd_in[241]
    DIRECTION OUTPUT ;
    USE SIGNAL ;
    SHAPE ABUTMENT ;
    PORT
      LAYER met2 ;
      RECT 418.530 0.000 418.670 0.420 ;
    END
  END w0_wd_in[241]
  PIN w0_wd_in[242]
    DIRECTION OUTPUT ;
    USE SIGNAL ;
    SHAPE ABUTMENT ;
    PORT
      LAYER met2 ;
      RECT 422.210 0.000 422.350 0.420 ;
    END
  END w0_wd_in[242]
  PIN w0_wd_in[243]
    DIRECTION OUTPUT ;
    USE SIGNAL ;
    SHAPE ABUTMENT ;
    PORT
      LAYER met2 ;
      RECT 425.890 0.000 426.030 0.420 ;
    END
  END w0_wd_in[243]
  PIN w0_wd_in[244]
    DIRECTION OUTPUT ;
    USE SIGNAL ;
    SHAPE ABUTMENT ;
    PORT
      LAYER met2 ;
      RECT 429.570 0.000 429.710 0.420 ;
    END
  END w0_wd_in[244]
  PIN w0_wd_in[245]
    DIRECTION OUTPUT ;
    USE SIGNAL ;
    SHAPE ABUTMENT ;
    PORT
      LAYER met2 ;
      RECT 433.250 0.000 433.390 0.420 ;
    END
  END w0_wd_in[245]
  PIN w0_wd_in[246]
    DIRECTION OUTPUT ;
    USE SIGNAL ;
    SHAPE ABUTMENT ;
    PORT
      LAYER met2 ;
      RECT 436.930 0.000 437.070 0.420 ;
    END
  END w0_wd_in[246]
  PIN w0_wd_in[247]
    DIRECTION OUTPUT ;
    USE SIGNAL ;
    SHAPE ABUTMENT ;
    PORT
      LAYER met2 ;
      RECT 440.610 0.000 440.750 0.420 ;
    END
  END w0_wd_in[247]
  PIN w0_wd_in[248]
    DIRECTION OUTPUT ;
    USE SIGNAL ;
    SHAPE ABUTMENT ;
    PORT
      LAYER met2 ;
      RECT 444.290 0.000 444.430 0.420 ;
    END
  END w0_wd_in[248]
  PIN w0_wd_in[249]
    DIRECTION OUTPUT ;
    USE SIGNAL ;
    SHAPE ABUTMENT ;
    PORT
      LAYER met2 ;
      RECT 447.970 0.000 448.110 0.420 ;
    END
  END w0_wd_in[249]
  PIN w0_wd_in[250]
    DIRECTION OUTPUT ;
    USE SIGNAL ;
    SHAPE ABUTMENT ;
    PORT
      LAYER met2 ;
      RECT 451.650 0.000 451.790 0.420 ;
    END
  END w0_wd_in[250]
  PIN w0_wd_in[251]
    DIRECTION OUTPUT ;
    USE SIGNAL ;
    SHAPE ABUTMENT ;
    PORT
      LAYER met2 ;
      RECT 455.330 0.000 455.470 0.420 ;
    END
  END w0_wd_in[251]
  PIN w0_wd_in[252]
    DIRECTION OUTPUT ;
    USE SIGNAL ;
    SHAPE ABUTMENT ;
    PORT
      LAYER met2 ;
      RECT 459.010 0.000 459.150 0.420 ;
    END
  END w0_wd_in[252]
  PIN w0_wd_in[253]
    DIRECTION OUTPUT ;
    USE SIGNAL ;
    SHAPE ABUTMENT ;
    PORT
      LAYER met2 ;
      RECT 462.690 0.000 462.830 0.420 ;
    END
  END w0_wd_in[253]
  PIN w0_wd_in[254]
    DIRECTION OUTPUT ;
    USE SIGNAL ;
    SHAPE ABUTMENT ;
    PORT
      LAYER met2 ;
      RECT 466.370 0.000 466.510 0.420 ;
    END
  END w0_wd_in[254]
  PIN w0_wd_in[255]
    DIRECTION OUTPUT ;
    USE SIGNAL ;
    SHAPE ABUTMENT ;
    PORT
      LAYER met2 ;
      RECT 470.050 0.000 470.190 0.420 ;
    END
  END w0_wd_in[255]
  PIN r0_rd_out[0]
    DIRECTION OUTPUT ;
    USE SIGNAL ;
    SHAPE ABUTMENT ;
    PORT
      LAYER met2 ;
      RECT 473.730 0.000 473.870 0.420 ;
    END
  END r0_rd_out[0]
  PIN r0_rd_out[1]
    DIRECTION OUTPUT ;
    USE SIGNAL ;
    SHAPE ABUTMENT ;
    PORT
      LAYER met2 ;
      RECT 477.410 0.000 477.550 0.420 ;
    END
  END r0_rd_out[1]
  PIN r0_rd_out[2]
    DIRECTION OUTPUT ;
    USE SIGNAL ;
    SHAPE ABUTMENT ;
    PORT
      LAYER met2 ;
      RECT 481.090 0.000 481.230 0.420 ;
    END
  END r0_rd_out[2]
  PIN r0_rd_out[3]
    DIRECTION OUTPUT ;
    USE SIGNAL ;
    SHAPE ABUTMENT ;
    PORT
      LAYER met2 ;
      RECT 484.770 0.000 484.910 0.420 ;
    END
  END r0_rd_out[3]
  PIN r0_rd_out[4]
    DIRECTION OUTPUT ;
    USE SIGNAL ;
    SHAPE ABUTMENT ;
    PORT
      LAYER met2 ;
      RECT 488.450 0.000 488.590 0.420 ;
    END
  END r0_rd_out[4]
  PIN r0_rd_out[5]
    DIRECTION OUTPUT ;
    USE SIGNAL ;
    SHAPE ABUTMENT ;
    PORT
      LAYER met2 ;
      RECT 492.130 0.000 492.270 0.420 ;
    END
  END r0_rd_out[5]
  PIN r0_rd_out[6]
    DIRECTION OUTPUT ;
    USE SIGNAL ;
    SHAPE ABUTMENT ;
    PORT
      LAYER met2 ;
      RECT 495.810 0.000 495.950 0.420 ;
    END
  END r0_rd_out[6]
  PIN r0_rd_out[7]
    DIRECTION OUTPUT ;
    USE SIGNAL ;
    SHAPE ABUTMENT ;
    PORT
      LAYER met2 ;
      RECT 499.490 0.000 499.630 0.420 ;
    END
  END r0_rd_out[7]
  PIN r0_rd_out[8]
    DIRECTION OUTPUT ;
    USE SIGNAL ;
    SHAPE ABUTMENT ;
    PORT
      LAYER met2 ;
      RECT 503.170 0.000 503.310 0.420 ;
    END
  END r0_rd_out[8]
  PIN r0_rd_out[9]
    DIRECTION OUTPUT ;
    USE SIGNAL ;
    SHAPE ABUTMENT ;
    PORT
      LAYER met2 ;
      RECT 506.850 0.000 506.990 0.420 ;
    END
  END r0_rd_out[9]
  PIN r0_rd_out[10]
    DIRECTION OUTPUT ;
    USE SIGNAL ;
    SHAPE ABUTMENT ;
    PORT
      LAYER met2 ;
      RECT 510.530 0.000 510.670 0.420 ;
    END
  END r0_rd_out[10]
  PIN r0_rd_out[11]
    DIRECTION OUTPUT ;
    USE SIGNAL ;
    SHAPE ABUTMENT ;
    PORT
      LAYER met2 ;
      RECT 514.210 0.000 514.350 0.420 ;
    END
  END r0_rd_out[11]
  PIN r0_rd_out[12]
    DIRECTION OUTPUT ;
    USE SIGNAL ;
    SHAPE ABUTMENT ;
    PORT
      LAYER met2 ;
      RECT 517.890 0.000 518.030 0.420 ;
    END
  END r0_rd_out[12]
  PIN r0_rd_out[13]
    DIRECTION OUTPUT ;
    USE SIGNAL ;
    SHAPE ABUTMENT ;
    PORT
      LAYER met2 ;
      RECT 521.570 0.000 521.710 0.420 ;
    END
  END r0_rd_out[13]
  PIN r0_rd_out[14]
    DIRECTION OUTPUT ;
    USE SIGNAL ;
    SHAPE ABUTMENT ;
    PORT
      LAYER met2 ;
      RECT 525.250 0.000 525.390 0.420 ;
    END
  END r0_rd_out[14]
  PIN r0_rd_out[15]
    DIRECTION OUTPUT ;
    USE SIGNAL ;
    SHAPE ABUTMENT ;
    PORT
      LAYER met2 ;
      RECT 528.930 0.000 529.070 0.420 ;
    END
  END r0_rd_out[15]
  PIN r0_rd_out[16]
    DIRECTION OUTPUT ;
    USE SIGNAL ;
    SHAPE ABUTMENT ;
    PORT
      LAYER met2 ;
      RECT 532.610 0.000 532.750 0.420 ;
    END
  END r0_rd_out[16]
  PIN r0_rd_out[17]
    DIRECTION OUTPUT ;
    USE SIGNAL ;
    SHAPE ABUTMENT ;
    PORT
      LAYER met2 ;
      RECT 536.290 0.000 536.430 0.420 ;
    END
  END r0_rd_out[17]
  PIN r0_rd_out[18]
    DIRECTION OUTPUT ;
    USE SIGNAL ;
    SHAPE ABUTMENT ;
    PORT
      LAYER met2 ;
      RECT 539.970 0.000 540.110 0.420 ;
    END
  END r0_rd_out[18]
  PIN r0_rd_out[19]
    DIRECTION OUTPUT ;
    USE SIGNAL ;
    SHAPE ABUTMENT ;
    PORT
      LAYER met2 ;
      RECT 543.650 0.000 543.790 0.420 ;
    END
  END r0_rd_out[19]
  PIN r0_rd_out[20]
    DIRECTION OUTPUT ;
    USE SIGNAL ;
    SHAPE ABUTMENT ;
    PORT
      LAYER met2 ;
      RECT 547.330 0.000 547.470 0.420 ;
    END
  END r0_rd_out[20]
  PIN r0_rd_out[21]
    DIRECTION OUTPUT ;
    USE SIGNAL ;
    SHAPE ABUTMENT ;
    PORT
      LAYER met2 ;
      RECT 551.010 0.000 551.150 0.420 ;
    END
  END r0_rd_out[21]
  PIN r0_rd_out[22]
    DIRECTION OUTPUT ;
    USE SIGNAL ;
    SHAPE ABUTMENT ;
    PORT
      LAYER met2 ;
      RECT 554.690 0.000 554.830 0.420 ;
    END
  END r0_rd_out[22]
  PIN r0_rd_out[23]
    DIRECTION OUTPUT ;
    USE SIGNAL ;
    SHAPE ABUTMENT ;
    PORT
      LAYER met2 ;
      RECT 558.370 0.000 558.510 0.420 ;
    END
  END r0_rd_out[23]
  PIN r0_rd_out[24]
    DIRECTION OUTPUT ;
    USE SIGNAL ;
    SHAPE ABUTMENT ;
    PORT
      LAYER met2 ;
      RECT 562.050 0.000 562.190 0.420 ;
    END
  END r0_rd_out[24]
  PIN r0_rd_out[25]
    DIRECTION OUTPUT ;
    USE SIGNAL ;
    SHAPE ABUTMENT ;
    PORT
      LAYER met2 ;
      RECT 565.730 0.000 565.870 0.420 ;
    END
  END r0_rd_out[25]
  PIN r0_rd_out[26]
    DIRECTION OUTPUT ;
    USE SIGNAL ;
    SHAPE ABUTMENT ;
    PORT
      LAYER met2 ;
      RECT 569.410 0.000 569.550 0.420 ;
    END
  END r0_rd_out[26]
  PIN r0_rd_out[27]
    DIRECTION OUTPUT ;
    USE SIGNAL ;
    SHAPE ABUTMENT ;
    PORT
      LAYER met2 ;
      RECT 573.090 0.000 573.230 0.420 ;
    END
  END r0_rd_out[27]
  PIN r0_rd_out[28]
    DIRECTION OUTPUT ;
    USE SIGNAL ;
    SHAPE ABUTMENT ;
    PORT
      LAYER met2 ;
      RECT 576.770 0.000 576.910 0.420 ;
    END
  END r0_rd_out[28]
  PIN r0_rd_out[29]
    DIRECTION OUTPUT ;
    USE SIGNAL ;
    SHAPE ABUTMENT ;
    PORT
      LAYER met2 ;
      RECT 580.450 0.000 580.590 0.420 ;
    END
  END r0_rd_out[29]
  PIN r0_rd_out[30]
    DIRECTION OUTPUT ;
    USE SIGNAL ;
    SHAPE ABUTMENT ;
    PORT
      LAYER met2 ;
      RECT 584.130 0.000 584.270 0.420 ;
    END
  END r0_rd_out[30]
  PIN r0_rd_out[31]
    DIRECTION OUTPUT ;
    USE SIGNAL ;
    SHAPE ABUTMENT ;
    PORT
      LAYER met2 ;
      RECT 587.810 0.000 587.950 0.420 ;
    END
  END r0_rd_out[31]
  PIN r0_rd_out[32]
    DIRECTION OUTPUT ;
    USE SIGNAL ;
    SHAPE ABUTMENT ;
    PORT
      LAYER met2 ;
      RECT 591.490 0.000 591.630 0.420 ;
    END
  END r0_rd_out[32]
  PIN r0_rd_out[33]
    DIRECTION OUTPUT ;
    USE SIGNAL ;
    SHAPE ABUTMENT ;
    PORT
      LAYER met2 ;
      RECT 595.170 0.000 595.310 0.420 ;
    END
  END r0_rd_out[33]
  PIN r0_rd_out[34]
    DIRECTION OUTPUT ;
    USE SIGNAL ;
    SHAPE ABUTMENT ;
    PORT
      LAYER met2 ;
      RECT 598.850 0.000 598.990 0.420 ;
    END
  END r0_rd_out[34]
  PIN r0_rd_out[35]
    DIRECTION OUTPUT ;
    USE SIGNAL ;
    SHAPE ABUTMENT ;
    PORT
      LAYER met2 ;
      RECT 602.530 0.000 602.670 0.420 ;
    END
  END r0_rd_out[35]
  PIN r0_rd_out[36]
    DIRECTION OUTPUT ;
    USE SIGNAL ;
    SHAPE ABUTMENT ;
    PORT
      LAYER met2 ;
      RECT 606.210 0.000 606.350 0.420 ;
    END
  END r0_rd_out[36]
  PIN r0_rd_out[37]
    DIRECTION OUTPUT ;
    USE SIGNAL ;
    SHAPE ABUTMENT ;
    PORT
      LAYER met2 ;
      RECT 609.890 0.000 610.030 0.420 ;
    END
  END r0_rd_out[37]
  PIN r0_rd_out[38]
    DIRECTION OUTPUT ;
    USE SIGNAL ;
    SHAPE ABUTMENT ;
    PORT
      LAYER met2 ;
      RECT 613.570 0.000 613.710 0.420 ;
    END
  END r0_rd_out[38]
  PIN r0_rd_out[39]
    DIRECTION OUTPUT ;
    USE SIGNAL ;
    SHAPE ABUTMENT ;
    PORT
      LAYER met2 ;
      RECT 617.250 0.000 617.390 0.420 ;
    END
  END r0_rd_out[39]
  PIN r0_rd_out[40]
    DIRECTION OUTPUT ;
    USE SIGNAL ;
    SHAPE ABUTMENT ;
    PORT
      LAYER met2 ;
      RECT 620.930 0.000 621.070 0.420 ;
    END
  END r0_rd_out[40]
  PIN r0_rd_out[41]
    DIRECTION OUTPUT ;
    USE SIGNAL ;
    SHAPE ABUTMENT ;
    PORT
      LAYER met2 ;
      RECT 624.610 0.000 624.750 0.420 ;
    END
  END r0_rd_out[41]
  PIN r0_rd_out[42]
    DIRECTION OUTPUT ;
    USE SIGNAL ;
    SHAPE ABUTMENT ;
    PORT
      LAYER met2 ;
      RECT 628.290 0.000 628.430 0.420 ;
    END
  END r0_rd_out[42]
  PIN r0_rd_out[43]
    DIRECTION OUTPUT ;
    USE SIGNAL ;
    SHAPE ABUTMENT ;
    PORT
      LAYER met2 ;
      RECT 631.970 0.000 632.110 0.420 ;
    END
  END r0_rd_out[43]
  PIN r0_rd_out[44]
    DIRECTION OUTPUT ;
    USE SIGNAL ;
    SHAPE ABUTMENT ;
    PORT
      LAYER met2 ;
      RECT 635.650 0.000 635.790 0.420 ;
    END
  END r0_rd_out[44]
  PIN r0_rd_out[45]
    DIRECTION OUTPUT ;
    USE SIGNAL ;
    SHAPE ABUTMENT ;
    PORT
      LAYER met2 ;
      RECT 639.330 0.000 639.470 0.420 ;
    END
  END r0_rd_out[45]
  PIN r0_rd_out[46]
    DIRECTION OUTPUT ;
    USE SIGNAL ;
    SHAPE ABUTMENT ;
    PORT
      LAYER met2 ;
      RECT 643.010 0.000 643.150 0.420 ;
    END
  END r0_rd_out[46]
  PIN r0_rd_out[47]
    DIRECTION OUTPUT ;
    USE SIGNAL ;
    SHAPE ABUTMENT ;
    PORT
      LAYER met2 ;
      RECT 646.690 0.000 646.830 0.420 ;
    END
  END r0_rd_out[47]
  PIN r0_rd_out[48]
    DIRECTION OUTPUT ;
    USE SIGNAL ;
    SHAPE ABUTMENT ;
    PORT
      LAYER met2 ;
      RECT 650.370 0.000 650.510 0.420 ;
    END
  END r0_rd_out[48]
  PIN r0_rd_out[49]
    DIRECTION OUTPUT ;
    USE SIGNAL ;
    SHAPE ABUTMENT ;
    PORT
      LAYER met2 ;
      RECT 654.050 0.000 654.190 0.420 ;
    END
  END r0_rd_out[49]
  PIN r0_rd_out[50]
    DIRECTION OUTPUT ;
    USE SIGNAL ;
    SHAPE ABUTMENT ;
    PORT
      LAYER met2 ;
      RECT 657.730 0.000 657.870 0.420 ;
    END
  END r0_rd_out[50]
  PIN r0_rd_out[51]
    DIRECTION OUTPUT ;
    USE SIGNAL ;
    SHAPE ABUTMENT ;
    PORT
      LAYER met2 ;
      RECT 661.410 0.000 661.550 0.420 ;
    END
  END r0_rd_out[51]
  PIN r0_rd_out[52]
    DIRECTION OUTPUT ;
    USE SIGNAL ;
    SHAPE ABUTMENT ;
    PORT
      LAYER met2 ;
      RECT 665.090 0.000 665.230 0.420 ;
    END
  END r0_rd_out[52]
  PIN r0_rd_out[53]
    DIRECTION OUTPUT ;
    USE SIGNAL ;
    SHAPE ABUTMENT ;
    PORT
      LAYER met2 ;
      RECT 668.770 0.000 668.910 0.420 ;
    END
  END r0_rd_out[53]
  PIN r0_rd_out[54]
    DIRECTION OUTPUT ;
    USE SIGNAL ;
    SHAPE ABUTMENT ;
    PORT
      LAYER met2 ;
      RECT 672.450 0.000 672.590 0.420 ;
    END
  END r0_rd_out[54]
  PIN r0_rd_out[55]
    DIRECTION OUTPUT ;
    USE SIGNAL ;
    SHAPE ABUTMENT ;
    PORT
      LAYER met2 ;
      RECT 676.130 0.000 676.270 0.420 ;
    END
  END r0_rd_out[55]
  PIN r0_rd_out[56]
    DIRECTION OUTPUT ;
    USE SIGNAL ;
    SHAPE ABUTMENT ;
    PORT
      LAYER met2 ;
      RECT 679.810 0.000 679.950 0.420 ;
    END
  END r0_rd_out[56]
  PIN r0_rd_out[57]
    DIRECTION OUTPUT ;
    USE SIGNAL ;
    SHAPE ABUTMENT ;
    PORT
      LAYER met2 ;
      RECT 683.490 0.000 683.630 0.420 ;
    END
  END r0_rd_out[57]
  PIN r0_rd_out[58]
    DIRECTION OUTPUT ;
    USE SIGNAL ;
    SHAPE ABUTMENT ;
    PORT
      LAYER met2 ;
      RECT 687.170 0.000 687.310 0.420 ;
    END
  END r0_rd_out[58]
  PIN r0_rd_out[59]
    DIRECTION OUTPUT ;
    USE SIGNAL ;
    SHAPE ABUTMENT ;
    PORT
      LAYER met2 ;
      RECT 690.850 0.000 690.990 0.420 ;
    END
  END r0_rd_out[59]
  PIN r0_rd_out[60]
    DIRECTION OUTPUT ;
    USE SIGNAL ;
    SHAPE ABUTMENT ;
    PORT
      LAYER met2 ;
      RECT 694.530 0.000 694.670 0.420 ;
    END
  END r0_rd_out[60]
  PIN r0_rd_out[61]
    DIRECTION OUTPUT ;
    USE SIGNAL ;
    SHAPE ABUTMENT ;
    PORT
      LAYER met2 ;
      RECT 698.210 0.000 698.350 0.420 ;
    END
  END r0_rd_out[61]
  PIN r0_rd_out[62]
    DIRECTION OUTPUT ;
    USE SIGNAL ;
    SHAPE ABUTMENT ;
    PORT
      LAYER met2 ;
      RECT 701.890 0.000 702.030 0.420 ;
    END
  END r0_rd_out[62]
  PIN r0_rd_out[63]
    DIRECTION OUTPUT ;
    USE SIGNAL ;
    SHAPE ABUTMENT ;
    PORT
      LAYER met2 ;
      RECT 705.570 0.000 705.710 0.420 ;
    END
  END r0_rd_out[63]
  PIN r0_rd_out[64]
    DIRECTION OUTPUT ;
    USE SIGNAL ;
    SHAPE ABUTMENT ;
    PORT
      LAYER met2 ;
      RECT 709.250 0.000 709.390 0.420 ;
    END
  END r0_rd_out[64]
  PIN r0_rd_out[65]
    DIRECTION OUTPUT ;
    USE SIGNAL ;
    SHAPE ABUTMENT ;
    PORT
      LAYER met2 ;
      RECT 712.930 0.000 713.070 0.420 ;
    END
  END r0_rd_out[65]
  PIN r0_rd_out[66]
    DIRECTION OUTPUT ;
    USE SIGNAL ;
    SHAPE ABUTMENT ;
    PORT
      LAYER met2 ;
      RECT 716.610 0.000 716.750 0.420 ;
    END
  END r0_rd_out[66]
  PIN r0_rd_out[67]
    DIRECTION OUTPUT ;
    USE SIGNAL ;
    SHAPE ABUTMENT ;
    PORT
      LAYER met2 ;
      RECT 720.290 0.000 720.430 0.420 ;
    END
  END r0_rd_out[67]
  PIN r0_rd_out[68]
    DIRECTION OUTPUT ;
    USE SIGNAL ;
    SHAPE ABUTMENT ;
    PORT
      LAYER met2 ;
      RECT 723.970 0.000 724.110 0.420 ;
    END
  END r0_rd_out[68]
  PIN r0_rd_out[69]
    DIRECTION OUTPUT ;
    USE SIGNAL ;
    SHAPE ABUTMENT ;
    PORT
      LAYER met2 ;
      RECT 727.650 0.000 727.790 0.420 ;
    END
  END r0_rd_out[69]
  PIN r0_rd_out[70]
    DIRECTION OUTPUT ;
    USE SIGNAL ;
    SHAPE ABUTMENT ;
    PORT
      LAYER met2 ;
      RECT 731.330 0.000 731.470 0.420 ;
    END
  END r0_rd_out[70]
  PIN r0_rd_out[71]
    DIRECTION OUTPUT ;
    USE SIGNAL ;
    SHAPE ABUTMENT ;
    PORT
      LAYER met2 ;
      RECT 735.010 0.000 735.150 0.420 ;
    END
  END r0_rd_out[71]
  PIN r0_rd_out[72]
    DIRECTION OUTPUT ;
    USE SIGNAL ;
    SHAPE ABUTMENT ;
    PORT
      LAYER met2 ;
      RECT 738.690 0.000 738.830 0.420 ;
    END
  END r0_rd_out[72]
  PIN r0_rd_out[73]
    DIRECTION OUTPUT ;
    USE SIGNAL ;
    SHAPE ABUTMENT ;
    PORT
      LAYER met2 ;
      RECT 742.370 0.000 742.510 0.420 ;
    END
  END r0_rd_out[73]
  PIN r0_rd_out[74]
    DIRECTION OUTPUT ;
    USE SIGNAL ;
    SHAPE ABUTMENT ;
    PORT
      LAYER met2 ;
      RECT 746.050 0.000 746.190 0.420 ;
    END
  END r0_rd_out[74]
  PIN r0_rd_out[75]
    DIRECTION OUTPUT ;
    USE SIGNAL ;
    SHAPE ABUTMENT ;
    PORT
      LAYER met2 ;
      RECT 749.730 0.000 749.870 0.420 ;
    END
  END r0_rd_out[75]
  PIN r0_rd_out[76]
    DIRECTION OUTPUT ;
    USE SIGNAL ;
    SHAPE ABUTMENT ;
    PORT
      LAYER met2 ;
      RECT 753.410 0.000 753.550 0.420 ;
    END
  END r0_rd_out[76]
  PIN r0_rd_out[77]
    DIRECTION OUTPUT ;
    USE SIGNAL ;
    SHAPE ABUTMENT ;
    PORT
      LAYER met2 ;
      RECT 757.090 0.000 757.230 0.420 ;
    END
  END r0_rd_out[77]
  PIN r0_rd_out[78]
    DIRECTION OUTPUT ;
    USE SIGNAL ;
    SHAPE ABUTMENT ;
    PORT
      LAYER met2 ;
      RECT 760.770 0.000 760.910 0.420 ;
    END
  END r0_rd_out[78]
  PIN r0_rd_out[79]
    DIRECTION OUTPUT ;
    USE SIGNAL ;
    SHAPE ABUTMENT ;
    PORT
      LAYER met2 ;
      RECT 764.450 0.000 764.590 0.420 ;
    END
  END r0_rd_out[79]
  PIN r0_rd_out[80]
    DIRECTION OUTPUT ;
    USE SIGNAL ;
    SHAPE ABUTMENT ;
    PORT
      LAYER met2 ;
      RECT 768.130 0.000 768.270 0.420 ;
    END
  END r0_rd_out[80]
  PIN r0_rd_out[81]
    DIRECTION OUTPUT ;
    USE SIGNAL ;
    SHAPE ABUTMENT ;
    PORT
      LAYER met2 ;
      RECT 771.810 0.000 771.950 0.420 ;
    END
  END r0_rd_out[81]
  PIN r0_rd_out[82]
    DIRECTION OUTPUT ;
    USE SIGNAL ;
    SHAPE ABUTMENT ;
    PORT
      LAYER met2 ;
      RECT 775.490 0.000 775.630 0.420 ;
    END
  END r0_rd_out[82]
  PIN r0_rd_out[83]
    DIRECTION OUTPUT ;
    USE SIGNAL ;
    SHAPE ABUTMENT ;
    PORT
      LAYER met2 ;
      RECT 779.170 0.000 779.310 0.420 ;
    END
  END r0_rd_out[83]
  PIN r0_rd_out[84]
    DIRECTION OUTPUT ;
    USE SIGNAL ;
    SHAPE ABUTMENT ;
    PORT
      LAYER met2 ;
      RECT 782.850 0.000 782.990 0.420 ;
    END
  END r0_rd_out[84]
  PIN r0_rd_out[85]
    DIRECTION OUTPUT ;
    USE SIGNAL ;
    SHAPE ABUTMENT ;
    PORT
      LAYER met2 ;
      RECT 786.530 0.000 786.670 0.420 ;
    END
  END r0_rd_out[85]
  PIN r0_rd_out[86]
    DIRECTION OUTPUT ;
    USE SIGNAL ;
    SHAPE ABUTMENT ;
    PORT
      LAYER met2 ;
      RECT 790.210 0.000 790.350 0.420 ;
    END
  END r0_rd_out[86]
  PIN r0_rd_out[87]
    DIRECTION OUTPUT ;
    USE SIGNAL ;
    SHAPE ABUTMENT ;
    PORT
      LAYER met2 ;
      RECT 793.890 0.000 794.030 0.420 ;
    END
  END r0_rd_out[87]
  PIN r0_rd_out[88]
    DIRECTION OUTPUT ;
    USE SIGNAL ;
    SHAPE ABUTMENT ;
    PORT
      LAYER met2 ;
      RECT 797.570 0.000 797.710 0.420 ;
    END
  END r0_rd_out[88]
  PIN r0_rd_out[89]
    DIRECTION OUTPUT ;
    USE SIGNAL ;
    SHAPE ABUTMENT ;
    PORT
      LAYER met2 ;
      RECT 801.250 0.000 801.390 0.420 ;
    END
  END r0_rd_out[89]
  PIN r0_rd_out[90]
    DIRECTION OUTPUT ;
    USE SIGNAL ;
    SHAPE ABUTMENT ;
    PORT
      LAYER met2 ;
      RECT 804.930 0.000 805.070 0.420 ;
    END
  END r0_rd_out[90]
  PIN r0_rd_out[91]
    DIRECTION OUTPUT ;
    USE SIGNAL ;
    SHAPE ABUTMENT ;
    PORT
      LAYER met2 ;
      RECT 808.610 0.000 808.750 0.420 ;
    END
  END r0_rd_out[91]
  PIN r0_rd_out[92]
    DIRECTION OUTPUT ;
    USE SIGNAL ;
    SHAPE ABUTMENT ;
    PORT
      LAYER met2 ;
      RECT 812.290 0.000 812.430 0.420 ;
    END
  END r0_rd_out[92]
  PIN r0_rd_out[93]
    DIRECTION OUTPUT ;
    USE SIGNAL ;
    SHAPE ABUTMENT ;
    PORT
      LAYER met2 ;
      RECT 815.970 0.000 816.110 0.420 ;
    END
  END r0_rd_out[93]
  PIN r0_rd_out[94]
    DIRECTION OUTPUT ;
    USE SIGNAL ;
    SHAPE ABUTMENT ;
    PORT
      LAYER met2 ;
      RECT 819.650 0.000 819.790 0.420 ;
    END
  END r0_rd_out[94]
  PIN r0_rd_out[95]
    DIRECTION OUTPUT ;
    USE SIGNAL ;
    SHAPE ABUTMENT ;
    PORT
      LAYER met2 ;
      RECT 823.330 0.000 823.470 0.420 ;
    END
  END r0_rd_out[95]
  PIN r0_rd_out[96]
    DIRECTION OUTPUT ;
    USE SIGNAL ;
    SHAPE ABUTMENT ;
    PORT
      LAYER met2 ;
      RECT 827.010 0.000 827.150 0.420 ;
    END
  END r0_rd_out[96]
  PIN r0_rd_out[97]
    DIRECTION OUTPUT ;
    USE SIGNAL ;
    SHAPE ABUTMENT ;
    PORT
      LAYER met2 ;
      RECT 830.690 0.000 830.830 0.420 ;
    END
  END r0_rd_out[97]
  PIN r0_rd_out[98]
    DIRECTION OUTPUT ;
    USE SIGNAL ;
    SHAPE ABUTMENT ;
    PORT
      LAYER met2 ;
      RECT 834.370 0.000 834.510 0.420 ;
    END
  END r0_rd_out[98]
  PIN r0_rd_out[99]
    DIRECTION OUTPUT ;
    USE SIGNAL ;
    SHAPE ABUTMENT ;
    PORT
      LAYER met2 ;
      RECT 838.050 0.000 838.190 0.420 ;
    END
  END r0_rd_out[99]
  PIN r0_rd_out[100]
    DIRECTION OUTPUT ;
    USE SIGNAL ;
    SHAPE ABUTMENT ;
    PORT
      LAYER met2 ;
      RECT 841.730 0.000 841.870 0.420 ;
    END
  END r0_rd_out[100]
  PIN r0_rd_out[101]
    DIRECTION OUTPUT ;
    USE SIGNAL ;
    SHAPE ABUTMENT ;
    PORT
      LAYER met2 ;
      RECT 845.410 0.000 845.550 0.420 ;
    END
  END r0_rd_out[101]
  PIN r0_rd_out[102]
    DIRECTION OUTPUT ;
    USE SIGNAL ;
    SHAPE ABUTMENT ;
    PORT
      LAYER met2 ;
      RECT 849.090 0.000 849.230 0.420 ;
    END
  END r0_rd_out[102]
  PIN r0_rd_out[103]
    DIRECTION OUTPUT ;
    USE SIGNAL ;
    SHAPE ABUTMENT ;
    PORT
      LAYER met2 ;
      RECT 852.770 0.000 852.910 0.420 ;
    END
  END r0_rd_out[103]
  PIN r0_rd_out[104]
    DIRECTION OUTPUT ;
    USE SIGNAL ;
    SHAPE ABUTMENT ;
    PORT
      LAYER met2 ;
      RECT 856.450 0.000 856.590 0.420 ;
    END
  END r0_rd_out[104]
  PIN r0_rd_out[105]
    DIRECTION OUTPUT ;
    USE SIGNAL ;
    SHAPE ABUTMENT ;
    PORT
      LAYER met2 ;
      RECT 860.130 0.000 860.270 0.420 ;
    END
  END r0_rd_out[105]
  PIN r0_rd_out[106]
    DIRECTION OUTPUT ;
    USE SIGNAL ;
    SHAPE ABUTMENT ;
    PORT
      LAYER met2 ;
      RECT 863.810 0.000 863.950 0.420 ;
    END
  END r0_rd_out[106]
  PIN r0_rd_out[107]
    DIRECTION OUTPUT ;
    USE SIGNAL ;
    SHAPE ABUTMENT ;
    PORT
      LAYER met2 ;
      RECT 867.490 0.000 867.630 0.420 ;
    END
  END r0_rd_out[107]
  PIN r0_rd_out[108]
    DIRECTION OUTPUT ;
    USE SIGNAL ;
    SHAPE ABUTMENT ;
    PORT
      LAYER met2 ;
      RECT 871.170 0.000 871.310 0.420 ;
    END
  END r0_rd_out[108]
  PIN r0_rd_out[109]
    DIRECTION OUTPUT ;
    USE SIGNAL ;
    SHAPE ABUTMENT ;
    PORT
      LAYER met2 ;
      RECT 874.850 0.000 874.990 0.420 ;
    END
  END r0_rd_out[109]
  PIN r0_rd_out[110]
    DIRECTION OUTPUT ;
    USE SIGNAL ;
    SHAPE ABUTMENT ;
    PORT
      LAYER met2 ;
      RECT 878.530 0.000 878.670 0.420 ;
    END
  END r0_rd_out[110]
  PIN r0_rd_out[111]
    DIRECTION OUTPUT ;
    USE SIGNAL ;
    SHAPE ABUTMENT ;
    PORT
      LAYER met2 ;
      RECT 882.210 0.000 882.350 0.420 ;
    END
  END r0_rd_out[111]
  PIN r0_rd_out[112]
    DIRECTION OUTPUT ;
    USE SIGNAL ;
    SHAPE ABUTMENT ;
    PORT
      LAYER met2 ;
      RECT 885.890 0.000 886.030 0.420 ;
    END
  END r0_rd_out[112]
  PIN r0_rd_out[113]
    DIRECTION OUTPUT ;
    USE SIGNAL ;
    SHAPE ABUTMENT ;
    PORT
      LAYER met2 ;
      RECT 889.570 0.000 889.710 0.420 ;
    END
  END r0_rd_out[113]
  PIN r0_rd_out[114]
    DIRECTION OUTPUT ;
    USE SIGNAL ;
    SHAPE ABUTMENT ;
    PORT
      LAYER met2 ;
      RECT 893.250 0.000 893.390 0.420 ;
    END
  END r0_rd_out[114]
  PIN r0_rd_out[115]
    DIRECTION OUTPUT ;
    USE SIGNAL ;
    SHAPE ABUTMENT ;
    PORT
      LAYER met2 ;
      RECT 896.930 0.000 897.070 0.420 ;
    END
  END r0_rd_out[115]
  PIN r0_rd_out[116]
    DIRECTION OUTPUT ;
    USE SIGNAL ;
    SHAPE ABUTMENT ;
    PORT
      LAYER met2 ;
      RECT 900.610 0.000 900.750 0.420 ;
    END
  END r0_rd_out[116]
  PIN r0_rd_out[117]
    DIRECTION OUTPUT ;
    USE SIGNAL ;
    SHAPE ABUTMENT ;
    PORT
      LAYER met2 ;
      RECT 904.290 0.000 904.430 0.420 ;
    END
  END r0_rd_out[117]
  PIN r0_rd_out[118]
    DIRECTION OUTPUT ;
    USE SIGNAL ;
    SHAPE ABUTMENT ;
    PORT
      LAYER met2 ;
      RECT 907.970 0.000 908.110 0.420 ;
    END
  END r0_rd_out[118]
  PIN r0_rd_out[119]
    DIRECTION OUTPUT ;
    USE SIGNAL ;
    SHAPE ABUTMENT ;
    PORT
      LAYER met2 ;
      RECT 911.650 0.000 911.790 0.420 ;
    END
  END r0_rd_out[119]
  PIN r0_rd_out[120]
    DIRECTION OUTPUT ;
    USE SIGNAL ;
    SHAPE ABUTMENT ;
    PORT
      LAYER met2 ;
      RECT 915.330 0.000 915.470 0.420 ;
    END
  END r0_rd_out[120]
  PIN r0_rd_out[121]
    DIRECTION OUTPUT ;
    USE SIGNAL ;
    SHAPE ABUTMENT ;
    PORT
      LAYER met2 ;
      RECT 919.010 0.000 919.150 0.420 ;
    END
  END r0_rd_out[121]
  PIN r0_rd_out[122]
    DIRECTION OUTPUT ;
    USE SIGNAL ;
    SHAPE ABUTMENT ;
    PORT
      LAYER met2 ;
      RECT 922.690 0.000 922.830 0.420 ;
    END
  END r0_rd_out[122]
  PIN r0_rd_out[123]
    DIRECTION OUTPUT ;
    USE SIGNAL ;
    SHAPE ABUTMENT ;
    PORT
      LAYER met2 ;
      RECT 926.370 0.000 926.510 0.420 ;
    END
  END r0_rd_out[123]
  PIN r0_rd_out[124]
    DIRECTION OUTPUT ;
    USE SIGNAL ;
    SHAPE ABUTMENT ;
    PORT
      LAYER met2 ;
      RECT 930.050 0.000 930.190 0.420 ;
    END
  END r0_rd_out[124]
  PIN r0_rd_out[125]
    DIRECTION OUTPUT ;
    USE SIGNAL ;
    SHAPE ABUTMENT ;
    PORT
      LAYER met2 ;
      RECT 933.730 0.000 933.870 0.420 ;
    END
  END r0_rd_out[125]
  PIN r0_rd_out[126]
    DIRECTION OUTPUT ;
    USE SIGNAL ;
    SHAPE ABUTMENT ;
    PORT
      LAYER met2 ;
      RECT 937.410 0.000 937.550 0.420 ;
    END
  END r0_rd_out[126]
  PIN r0_rd_out[127]
    DIRECTION OUTPUT ;
    USE SIGNAL ;
    SHAPE ABUTMENT ;
    PORT
      LAYER met2 ;
      RECT 941.090 0.000 941.230 0.420 ;
    END
  END r0_rd_out[127]
  PIN r0_rd_out[128]
    DIRECTION OUTPUT ;
    USE SIGNAL ;
    SHAPE ABUTMENT ;
    PORT
      LAYER met2 ;
      RECT 2.690 812.860 2.830 813.280 ;
    END
  END r0_rd_out[128]
  PIN r0_rd_out[129]
    DIRECTION OUTPUT ;
    USE SIGNAL ;
    SHAPE ABUTMENT ;
    PORT
      LAYER met2 ;
      RECT 10.050 812.860 10.190 813.280 ;
    END
  END r0_rd_out[129]
  PIN r0_rd_out[130]
    DIRECTION OUTPUT ;
    USE SIGNAL ;
    SHAPE ABUTMENT ;
    PORT
      LAYER met2 ;
      RECT 17.410 812.860 17.550 813.280 ;
    END
  END r0_rd_out[130]
  PIN r0_rd_out[131]
    DIRECTION OUTPUT ;
    USE SIGNAL ;
    SHAPE ABUTMENT ;
    PORT
      LAYER met2 ;
      RECT 24.770 812.860 24.910 813.280 ;
    END
  END r0_rd_out[131]
  PIN r0_rd_out[132]
    DIRECTION OUTPUT ;
    USE SIGNAL ;
    SHAPE ABUTMENT ;
    PORT
      LAYER met2 ;
      RECT 32.130 812.860 32.270 813.280 ;
    END
  END r0_rd_out[132]
  PIN r0_rd_out[133]
    DIRECTION OUTPUT ;
    USE SIGNAL ;
    SHAPE ABUTMENT ;
    PORT
      LAYER met2 ;
      RECT 39.490 812.860 39.630 813.280 ;
    END
  END r0_rd_out[133]
  PIN r0_rd_out[134]
    DIRECTION OUTPUT ;
    USE SIGNAL ;
    SHAPE ABUTMENT ;
    PORT
      LAYER met2 ;
      RECT 46.850 812.860 46.990 813.280 ;
    END
  END r0_rd_out[134]
  PIN r0_rd_out[135]
    DIRECTION OUTPUT ;
    USE SIGNAL ;
    SHAPE ABUTMENT ;
    PORT
      LAYER met2 ;
      RECT 54.210 812.860 54.350 813.280 ;
    END
  END r0_rd_out[135]
  PIN r0_rd_out[136]
    DIRECTION OUTPUT ;
    USE SIGNAL ;
    SHAPE ABUTMENT ;
    PORT
      LAYER met2 ;
      RECT 61.570 812.860 61.710 813.280 ;
    END
  END r0_rd_out[136]
  PIN r0_rd_out[137]
    DIRECTION OUTPUT ;
    USE SIGNAL ;
    SHAPE ABUTMENT ;
    PORT
      LAYER met2 ;
      RECT 68.930 812.860 69.070 813.280 ;
    END
  END r0_rd_out[137]
  PIN r0_rd_out[138]
    DIRECTION OUTPUT ;
    USE SIGNAL ;
    SHAPE ABUTMENT ;
    PORT
      LAYER met2 ;
      RECT 76.290 812.860 76.430 813.280 ;
    END
  END r0_rd_out[138]
  PIN r0_rd_out[139]
    DIRECTION OUTPUT ;
    USE SIGNAL ;
    SHAPE ABUTMENT ;
    PORT
      LAYER met2 ;
      RECT 83.650 812.860 83.790 813.280 ;
    END
  END r0_rd_out[139]
  PIN r0_rd_out[140]
    DIRECTION OUTPUT ;
    USE SIGNAL ;
    SHAPE ABUTMENT ;
    PORT
      LAYER met2 ;
      RECT 91.010 812.860 91.150 813.280 ;
    END
  END r0_rd_out[140]
  PIN r0_rd_out[141]
    DIRECTION OUTPUT ;
    USE SIGNAL ;
    SHAPE ABUTMENT ;
    PORT
      LAYER met2 ;
      RECT 98.370 812.860 98.510 813.280 ;
    END
  END r0_rd_out[141]
  PIN r0_rd_out[142]
    DIRECTION OUTPUT ;
    USE SIGNAL ;
    SHAPE ABUTMENT ;
    PORT
      LAYER met2 ;
      RECT 105.730 812.860 105.870 813.280 ;
    END
  END r0_rd_out[142]
  PIN r0_rd_out[143]
    DIRECTION OUTPUT ;
    USE SIGNAL ;
    SHAPE ABUTMENT ;
    PORT
      LAYER met2 ;
      RECT 113.090 812.860 113.230 813.280 ;
    END
  END r0_rd_out[143]
  PIN r0_rd_out[144]
    DIRECTION OUTPUT ;
    USE SIGNAL ;
    SHAPE ABUTMENT ;
    PORT
      LAYER met2 ;
      RECT 120.450 812.860 120.590 813.280 ;
    END
  END r0_rd_out[144]
  PIN r0_rd_out[145]
    DIRECTION OUTPUT ;
    USE SIGNAL ;
    SHAPE ABUTMENT ;
    PORT
      LAYER met2 ;
      RECT 127.810 812.860 127.950 813.280 ;
    END
  END r0_rd_out[145]
  PIN r0_rd_out[146]
    DIRECTION OUTPUT ;
    USE SIGNAL ;
    SHAPE ABUTMENT ;
    PORT
      LAYER met2 ;
      RECT 135.170 812.860 135.310 813.280 ;
    END
  END r0_rd_out[146]
  PIN r0_rd_out[147]
    DIRECTION OUTPUT ;
    USE SIGNAL ;
    SHAPE ABUTMENT ;
    PORT
      LAYER met2 ;
      RECT 142.530 812.860 142.670 813.280 ;
    END
  END r0_rd_out[147]
  PIN r0_rd_out[148]
    DIRECTION OUTPUT ;
    USE SIGNAL ;
    SHAPE ABUTMENT ;
    PORT
      LAYER met2 ;
      RECT 149.890 812.860 150.030 813.280 ;
    END
  END r0_rd_out[148]
  PIN r0_rd_out[149]
    DIRECTION OUTPUT ;
    USE SIGNAL ;
    SHAPE ABUTMENT ;
    PORT
      LAYER met2 ;
      RECT 157.250 812.860 157.390 813.280 ;
    END
  END r0_rd_out[149]
  PIN r0_rd_out[150]
    DIRECTION OUTPUT ;
    USE SIGNAL ;
    SHAPE ABUTMENT ;
    PORT
      LAYER met2 ;
      RECT 164.610 812.860 164.750 813.280 ;
    END
  END r0_rd_out[150]
  PIN r0_rd_out[151]
    DIRECTION OUTPUT ;
    USE SIGNAL ;
    SHAPE ABUTMENT ;
    PORT
      LAYER met2 ;
      RECT 171.970 812.860 172.110 813.280 ;
    END
  END r0_rd_out[151]
  PIN r0_rd_out[152]
    DIRECTION OUTPUT ;
    USE SIGNAL ;
    SHAPE ABUTMENT ;
    PORT
      LAYER met2 ;
      RECT 179.330 812.860 179.470 813.280 ;
    END
  END r0_rd_out[152]
  PIN r0_rd_out[153]
    DIRECTION OUTPUT ;
    USE SIGNAL ;
    SHAPE ABUTMENT ;
    PORT
      LAYER met2 ;
      RECT 186.690 812.860 186.830 813.280 ;
    END
  END r0_rd_out[153]
  PIN r0_rd_out[154]
    DIRECTION OUTPUT ;
    USE SIGNAL ;
    SHAPE ABUTMENT ;
    PORT
      LAYER met2 ;
      RECT 194.050 812.860 194.190 813.280 ;
    END
  END r0_rd_out[154]
  PIN r0_rd_out[155]
    DIRECTION OUTPUT ;
    USE SIGNAL ;
    SHAPE ABUTMENT ;
    PORT
      LAYER met2 ;
      RECT 201.410 812.860 201.550 813.280 ;
    END
  END r0_rd_out[155]
  PIN r0_rd_out[156]
    DIRECTION OUTPUT ;
    USE SIGNAL ;
    SHAPE ABUTMENT ;
    PORT
      LAYER met2 ;
      RECT 208.770 812.860 208.910 813.280 ;
    END
  END r0_rd_out[156]
  PIN r0_rd_out[157]
    DIRECTION OUTPUT ;
    USE SIGNAL ;
    SHAPE ABUTMENT ;
    PORT
      LAYER met2 ;
      RECT 216.130 812.860 216.270 813.280 ;
    END
  END r0_rd_out[157]
  PIN r0_rd_out[158]
    DIRECTION OUTPUT ;
    USE SIGNAL ;
    SHAPE ABUTMENT ;
    PORT
      LAYER met2 ;
      RECT 223.490 812.860 223.630 813.280 ;
    END
  END r0_rd_out[158]
  PIN r0_rd_out[159]
    DIRECTION OUTPUT ;
    USE SIGNAL ;
    SHAPE ABUTMENT ;
    PORT
      LAYER met2 ;
      RECT 230.850 812.860 230.990 813.280 ;
    END
  END r0_rd_out[159]
  PIN r0_rd_out[160]
    DIRECTION OUTPUT ;
    USE SIGNAL ;
    SHAPE ABUTMENT ;
    PORT
      LAYER met2 ;
      RECT 238.210 812.860 238.350 813.280 ;
    END
  END r0_rd_out[160]
  PIN r0_rd_out[161]
    DIRECTION OUTPUT ;
    USE SIGNAL ;
    SHAPE ABUTMENT ;
    PORT
      LAYER met2 ;
      RECT 245.570 812.860 245.710 813.280 ;
    END
  END r0_rd_out[161]
  PIN r0_rd_out[162]
    DIRECTION OUTPUT ;
    USE SIGNAL ;
    SHAPE ABUTMENT ;
    PORT
      LAYER met2 ;
      RECT 252.930 812.860 253.070 813.280 ;
    END
  END r0_rd_out[162]
  PIN r0_rd_out[163]
    DIRECTION OUTPUT ;
    USE SIGNAL ;
    SHAPE ABUTMENT ;
    PORT
      LAYER met2 ;
      RECT 260.290 812.860 260.430 813.280 ;
    END
  END r0_rd_out[163]
  PIN r0_rd_out[164]
    DIRECTION OUTPUT ;
    USE SIGNAL ;
    SHAPE ABUTMENT ;
    PORT
      LAYER met2 ;
      RECT 267.650 812.860 267.790 813.280 ;
    END
  END r0_rd_out[164]
  PIN r0_rd_out[165]
    DIRECTION OUTPUT ;
    USE SIGNAL ;
    SHAPE ABUTMENT ;
    PORT
      LAYER met2 ;
      RECT 275.010 812.860 275.150 813.280 ;
    END
  END r0_rd_out[165]
  PIN r0_rd_out[166]
    DIRECTION OUTPUT ;
    USE SIGNAL ;
    SHAPE ABUTMENT ;
    PORT
      LAYER met2 ;
      RECT 282.370 812.860 282.510 813.280 ;
    END
  END r0_rd_out[166]
  PIN r0_rd_out[167]
    DIRECTION OUTPUT ;
    USE SIGNAL ;
    SHAPE ABUTMENT ;
    PORT
      LAYER met2 ;
      RECT 289.730 812.860 289.870 813.280 ;
    END
  END r0_rd_out[167]
  PIN r0_rd_out[168]
    DIRECTION OUTPUT ;
    USE SIGNAL ;
    SHAPE ABUTMENT ;
    PORT
      LAYER met2 ;
      RECT 297.090 812.860 297.230 813.280 ;
    END
  END r0_rd_out[168]
  PIN r0_rd_out[169]
    DIRECTION OUTPUT ;
    USE SIGNAL ;
    SHAPE ABUTMENT ;
    PORT
      LAYER met2 ;
      RECT 304.450 812.860 304.590 813.280 ;
    END
  END r0_rd_out[169]
  PIN r0_rd_out[170]
    DIRECTION OUTPUT ;
    USE SIGNAL ;
    SHAPE ABUTMENT ;
    PORT
      LAYER met2 ;
      RECT 311.810 812.860 311.950 813.280 ;
    END
  END r0_rd_out[170]
  PIN r0_rd_out[171]
    DIRECTION OUTPUT ;
    USE SIGNAL ;
    SHAPE ABUTMENT ;
    PORT
      LAYER met2 ;
      RECT 319.170 812.860 319.310 813.280 ;
    END
  END r0_rd_out[171]
  PIN r0_rd_out[172]
    DIRECTION OUTPUT ;
    USE SIGNAL ;
    SHAPE ABUTMENT ;
    PORT
      LAYER met2 ;
      RECT 326.530 812.860 326.670 813.280 ;
    END
  END r0_rd_out[172]
  PIN r0_rd_out[173]
    DIRECTION OUTPUT ;
    USE SIGNAL ;
    SHAPE ABUTMENT ;
    PORT
      LAYER met2 ;
      RECT 333.890 812.860 334.030 813.280 ;
    END
  END r0_rd_out[173]
  PIN r0_rd_out[174]
    DIRECTION OUTPUT ;
    USE SIGNAL ;
    SHAPE ABUTMENT ;
    PORT
      LAYER met2 ;
      RECT 341.250 812.860 341.390 813.280 ;
    END
  END r0_rd_out[174]
  PIN r0_rd_out[175]
    DIRECTION OUTPUT ;
    USE SIGNAL ;
    SHAPE ABUTMENT ;
    PORT
      LAYER met2 ;
      RECT 348.610 812.860 348.750 813.280 ;
    END
  END r0_rd_out[175]
  PIN r0_rd_out[176]
    DIRECTION OUTPUT ;
    USE SIGNAL ;
    SHAPE ABUTMENT ;
    PORT
      LAYER met2 ;
      RECT 355.970 812.860 356.110 813.280 ;
    END
  END r0_rd_out[176]
  PIN r0_rd_out[177]
    DIRECTION OUTPUT ;
    USE SIGNAL ;
    SHAPE ABUTMENT ;
    PORT
      LAYER met2 ;
      RECT 363.330 812.860 363.470 813.280 ;
    END
  END r0_rd_out[177]
  PIN r0_rd_out[178]
    DIRECTION OUTPUT ;
    USE SIGNAL ;
    SHAPE ABUTMENT ;
    PORT
      LAYER met2 ;
      RECT 370.690 812.860 370.830 813.280 ;
    END
  END r0_rd_out[178]
  PIN r0_rd_out[179]
    DIRECTION OUTPUT ;
    USE SIGNAL ;
    SHAPE ABUTMENT ;
    PORT
      LAYER met2 ;
      RECT 378.050 812.860 378.190 813.280 ;
    END
  END r0_rd_out[179]
  PIN r0_rd_out[180]
    DIRECTION OUTPUT ;
    USE SIGNAL ;
    SHAPE ABUTMENT ;
    PORT
      LAYER met2 ;
      RECT 385.410 812.860 385.550 813.280 ;
    END
  END r0_rd_out[180]
  PIN r0_rd_out[181]
    DIRECTION OUTPUT ;
    USE SIGNAL ;
    SHAPE ABUTMENT ;
    PORT
      LAYER met2 ;
      RECT 392.770 812.860 392.910 813.280 ;
    END
  END r0_rd_out[181]
  PIN r0_rd_out[182]
    DIRECTION OUTPUT ;
    USE SIGNAL ;
    SHAPE ABUTMENT ;
    PORT
      LAYER met2 ;
      RECT 400.130 812.860 400.270 813.280 ;
    END
  END r0_rd_out[182]
  PIN r0_rd_out[183]
    DIRECTION OUTPUT ;
    USE SIGNAL ;
    SHAPE ABUTMENT ;
    PORT
      LAYER met2 ;
      RECT 407.490 812.860 407.630 813.280 ;
    END
  END r0_rd_out[183]
  PIN r0_rd_out[184]
    DIRECTION OUTPUT ;
    USE SIGNAL ;
    SHAPE ABUTMENT ;
    PORT
      LAYER met2 ;
      RECT 414.850 812.860 414.990 813.280 ;
    END
  END r0_rd_out[184]
  PIN r0_rd_out[185]
    DIRECTION OUTPUT ;
    USE SIGNAL ;
    SHAPE ABUTMENT ;
    PORT
      LAYER met2 ;
      RECT 422.210 812.860 422.350 813.280 ;
    END
  END r0_rd_out[185]
  PIN r0_rd_out[186]
    DIRECTION OUTPUT ;
    USE SIGNAL ;
    SHAPE ABUTMENT ;
    PORT
      LAYER met2 ;
      RECT 429.570 812.860 429.710 813.280 ;
    END
  END r0_rd_out[186]
  PIN r0_rd_out[187]
    DIRECTION OUTPUT ;
    USE SIGNAL ;
    SHAPE ABUTMENT ;
    PORT
      LAYER met2 ;
      RECT 436.930 812.860 437.070 813.280 ;
    END
  END r0_rd_out[187]
  PIN r0_rd_out[188]
    DIRECTION OUTPUT ;
    USE SIGNAL ;
    SHAPE ABUTMENT ;
    PORT
      LAYER met2 ;
      RECT 444.290 812.860 444.430 813.280 ;
    END
  END r0_rd_out[188]
  PIN r0_rd_out[189]
    DIRECTION OUTPUT ;
    USE SIGNAL ;
    SHAPE ABUTMENT ;
    PORT
      LAYER met2 ;
      RECT 451.650 812.860 451.790 813.280 ;
    END
  END r0_rd_out[189]
  PIN r0_rd_out[190]
    DIRECTION OUTPUT ;
    USE SIGNAL ;
    SHAPE ABUTMENT ;
    PORT
      LAYER met2 ;
      RECT 459.010 812.860 459.150 813.280 ;
    END
  END r0_rd_out[190]
  PIN r0_rd_out[191]
    DIRECTION OUTPUT ;
    USE SIGNAL ;
    SHAPE ABUTMENT ;
    PORT
      LAYER met2 ;
      RECT 466.370 812.860 466.510 813.280 ;
    END
  END r0_rd_out[191]
  PIN r0_rd_out[192]
    DIRECTION OUTPUT ;
    USE SIGNAL ;
    SHAPE ABUTMENT ;
    PORT
      LAYER met2 ;
      RECT 473.730 812.860 473.870 813.280 ;
    END
  END r0_rd_out[192]
  PIN r0_rd_out[193]
    DIRECTION OUTPUT ;
    USE SIGNAL ;
    SHAPE ABUTMENT ;
    PORT
      LAYER met2 ;
      RECT 481.090 812.860 481.230 813.280 ;
    END
  END r0_rd_out[193]
  PIN r0_rd_out[194]
    DIRECTION OUTPUT ;
    USE SIGNAL ;
    SHAPE ABUTMENT ;
    PORT
      LAYER met2 ;
      RECT 488.450 812.860 488.590 813.280 ;
    END
  END r0_rd_out[194]
  PIN r0_rd_out[195]
    DIRECTION OUTPUT ;
    USE SIGNAL ;
    SHAPE ABUTMENT ;
    PORT
      LAYER met2 ;
      RECT 495.810 812.860 495.950 813.280 ;
    END
  END r0_rd_out[195]
  PIN r0_rd_out[196]
    DIRECTION OUTPUT ;
    USE SIGNAL ;
    SHAPE ABUTMENT ;
    PORT
      LAYER met2 ;
      RECT 503.170 812.860 503.310 813.280 ;
    END
  END r0_rd_out[196]
  PIN r0_rd_out[197]
    DIRECTION OUTPUT ;
    USE SIGNAL ;
    SHAPE ABUTMENT ;
    PORT
      LAYER met2 ;
      RECT 510.530 812.860 510.670 813.280 ;
    END
  END r0_rd_out[197]
  PIN r0_rd_out[198]
    DIRECTION OUTPUT ;
    USE SIGNAL ;
    SHAPE ABUTMENT ;
    PORT
      LAYER met2 ;
      RECT 517.890 812.860 518.030 813.280 ;
    END
  END r0_rd_out[198]
  PIN r0_rd_out[199]
    DIRECTION OUTPUT ;
    USE SIGNAL ;
    SHAPE ABUTMENT ;
    PORT
      LAYER met2 ;
      RECT 525.250 812.860 525.390 813.280 ;
    END
  END r0_rd_out[199]
  PIN r0_rd_out[200]
    DIRECTION OUTPUT ;
    USE SIGNAL ;
    SHAPE ABUTMENT ;
    PORT
      LAYER met2 ;
      RECT 532.610 812.860 532.750 813.280 ;
    END
  END r0_rd_out[200]
  PIN r0_rd_out[201]
    DIRECTION OUTPUT ;
    USE SIGNAL ;
    SHAPE ABUTMENT ;
    PORT
      LAYER met2 ;
      RECT 539.970 812.860 540.110 813.280 ;
    END
  END r0_rd_out[201]
  PIN r0_rd_out[202]
    DIRECTION OUTPUT ;
    USE SIGNAL ;
    SHAPE ABUTMENT ;
    PORT
      LAYER met2 ;
      RECT 547.330 812.860 547.470 813.280 ;
    END
  END r0_rd_out[202]
  PIN r0_rd_out[203]
    DIRECTION OUTPUT ;
    USE SIGNAL ;
    SHAPE ABUTMENT ;
    PORT
      LAYER met2 ;
      RECT 554.690 812.860 554.830 813.280 ;
    END
  END r0_rd_out[203]
  PIN r0_rd_out[204]
    DIRECTION OUTPUT ;
    USE SIGNAL ;
    SHAPE ABUTMENT ;
    PORT
      LAYER met2 ;
      RECT 562.050 812.860 562.190 813.280 ;
    END
  END r0_rd_out[204]
  PIN r0_rd_out[205]
    DIRECTION OUTPUT ;
    USE SIGNAL ;
    SHAPE ABUTMENT ;
    PORT
      LAYER met2 ;
      RECT 569.410 812.860 569.550 813.280 ;
    END
  END r0_rd_out[205]
  PIN r0_rd_out[206]
    DIRECTION OUTPUT ;
    USE SIGNAL ;
    SHAPE ABUTMENT ;
    PORT
      LAYER met2 ;
      RECT 576.770 812.860 576.910 813.280 ;
    END
  END r0_rd_out[206]
  PIN r0_rd_out[207]
    DIRECTION OUTPUT ;
    USE SIGNAL ;
    SHAPE ABUTMENT ;
    PORT
      LAYER met2 ;
      RECT 584.130 812.860 584.270 813.280 ;
    END
  END r0_rd_out[207]
  PIN r0_rd_out[208]
    DIRECTION OUTPUT ;
    USE SIGNAL ;
    SHAPE ABUTMENT ;
    PORT
      LAYER met2 ;
      RECT 591.490 812.860 591.630 813.280 ;
    END
  END r0_rd_out[208]
  PIN r0_rd_out[209]
    DIRECTION OUTPUT ;
    USE SIGNAL ;
    SHAPE ABUTMENT ;
    PORT
      LAYER met2 ;
      RECT 598.850 812.860 598.990 813.280 ;
    END
  END r0_rd_out[209]
  PIN r0_rd_out[210]
    DIRECTION OUTPUT ;
    USE SIGNAL ;
    SHAPE ABUTMENT ;
    PORT
      LAYER met2 ;
      RECT 606.210 812.860 606.350 813.280 ;
    END
  END r0_rd_out[210]
  PIN r0_rd_out[211]
    DIRECTION OUTPUT ;
    USE SIGNAL ;
    SHAPE ABUTMENT ;
    PORT
      LAYER met2 ;
      RECT 613.570 812.860 613.710 813.280 ;
    END
  END r0_rd_out[211]
  PIN r0_rd_out[212]
    DIRECTION OUTPUT ;
    USE SIGNAL ;
    SHAPE ABUTMENT ;
    PORT
      LAYER met2 ;
      RECT 620.930 812.860 621.070 813.280 ;
    END
  END r0_rd_out[212]
  PIN r0_rd_out[213]
    DIRECTION OUTPUT ;
    USE SIGNAL ;
    SHAPE ABUTMENT ;
    PORT
      LAYER met2 ;
      RECT 628.290 812.860 628.430 813.280 ;
    END
  END r0_rd_out[213]
  PIN r0_rd_out[214]
    DIRECTION OUTPUT ;
    USE SIGNAL ;
    SHAPE ABUTMENT ;
    PORT
      LAYER met2 ;
      RECT 635.650 812.860 635.790 813.280 ;
    END
  END r0_rd_out[214]
  PIN r0_rd_out[215]
    DIRECTION OUTPUT ;
    USE SIGNAL ;
    SHAPE ABUTMENT ;
    PORT
      LAYER met2 ;
      RECT 643.010 812.860 643.150 813.280 ;
    END
  END r0_rd_out[215]
  PIN r0_rd_out[216]
    DIRECTION OUTPUT ;
    USE SIGNAL ;
    SHAPE ABUTMENT ;
    PORT
      LAYER met2 ;
      RECT 650.370 812.860 650.510 813.280 ;
    END
  END r0_rd_out[216]
  PIN r0_rd_out[217]
    DIRECTION OUTPUT ;
    USE SIGNAL ;
    SHAPE ABUTMENT ;
    PORT
      LAYER met2 ;
      RECT 657.730 812.860 657.870 813.280 ;
    END
  END r0_rd_out[217]
  PIN r0_rd_out[218]
    DIRECTION OUTPUT ;
    USE SIGNAL ;
    SHAPE ABUTMENT ;
    PORT
      LAYER met2 ;
      RECT 665.090 812.860 665.230 813.280 ;
    END
  END r0_rd_out[218]
  PIN r0_rd_out[219]
    DIRECTION OUTPUT ;
    USE SIGNAL ;
    SHAPE ABUTMENT ;
    PORT
      LAYER met2 ;
      RECT 672.450 812.860 672.590 813.280 ;
    END
  END r0_rd_out[219]
  PIN r0_rd_out[220]
    DIRECTION OUTPUT ;
    USE SIGNAL ;
    SHAPE ABUTMENT ;
    PORT
      LAYER met2 ;
      RECT 679.810 812.860 679.950 813.280 ;
    END
  END r0_rd_out[220]
  PIN r0_rd_out[221]
    DIRECTION OUTPUT ;
    USE SIGNAL ;
    SHAPE ABUTMENT ;
    PORT
      LAYER met2 ;
      RECT 687.170 812.860 687.310 813.280 ;
    END
  END r0_rd_out[221]
  PIN r0_rd_out[222]
    DIRECTION OUTPUT ;
    USE SIGNAL ;
    SHAPE ABUTMENT ;
    PORT
      LAYER met2 ;
      RECT 694.530 812.860 694.670 813.280 ;
    END
  END r0_rd_out[222]
  PIN r0_rd_out[223]
    DIRECTION OUTPUT ;
    USE SIGNAL ;
    SHAPE ABUTMENT ;
    PORT
      LAYER met2 ;
      RECT 701.890 812.860 702.030 813.280 ;
    END
  END r0_rd_out[223]
  PIN r0_rd_out[224]
    DIRECTION OUTPUT ;
    USE SIGNAL ;
    SHAPE ABUTMENT ;
    PORT
      LAYER met2 ;
      RECT 709.250 812.860 709.390 813.280 ;
    END
  END r0_rd_out[224]
  PIN r0_rd_out[225]
    DIRECTION OUTPUT ;
    USE SIGNAL ;
    SHAPE ABUTMENT ;
    PORT
      LAYER met2 ;
      RECT 716.610 812.860 716.750 813.280 ;
    END
  END r0_rd_out[225]
  PIN r0_rd_out[226]
    DIRECTION OUTPUT ;
    USE SIGNAL ;
    SHAPE ABUTMENT ;
    PORT
      LAYER met2 ;
      RECT 723.970 812.860 724.110 813.280 ;
    END
  END r0_rd_out[226]
  PIN r0_rd_out[227]
    DIRECTION OUTPUT ;
    USE SIGNAL ;
    SHAPE ABUTMENT ;
    PORT
      LAYER met2 ;
      RECT 731.330 812.860 731.470 813.280 ;
    END
  END r0_rd_out[227]
  PIN r0_rd_out[228]
    DIRECTION OUTPUT ;
    USE SIGNAL ;
    SHAPE ABUTMENT ;
    PORT
      LAYER met2 ;
      RECT 738.690 812.860 738.830 813.280 ;
    END
  END r0_rd_out[228]
  PIN r0_rd_out[229]
    DIRECTION OUTPUT ;
    USE SIGNAL ;
    SHAPE ABUTMENT ;
    PORT
      LAYER met2 ;
      RECT 746.050 812.860 746.190 813.280 ;
    END
  END r0_rd_out[229]
  PIN r0_rd_out[230]
    DIRECTION OUTPUT ;
    USE SIGNAL ;
    SHAPE ABUTMENT ;
    PORT
      LAYER met2 ;
      RECT 753.410 812.860 753.550 813.280 ;
    END
  END r0_rd_out[230]
  PIN r0_rd_out[231]
    DIRECTION OUTPUT ;
    USE SIGNAL ;
    SHAPE ABUTMENT ;
    PORT
      LAYER met2 ;
      RECT 760.770 812.860 760.910 813.280 ;
    END
  END r0_rd_out[231]
  PIN r0_rd_out[232]
    DIRECTION OUTPUT ;
    USE SIGNAL ;
    SHAPE ABUTMENT ;
    PORT
      LAYER met2 ;
      RECT 768.130 812.860 768.270 813.280 ;
    END
  END r0_rd_out[232]
  PIN r0_rd_out[233]
    DIRECTION OUTPUT ;
    USE SIGNAL ;
    SHAPE ABUTMENT ;
    PORT
      LAYER met2 ;
      RECT 775.490 812.860 775.630 813.280 ;
    END
  END r0_rd_out[233]
  PIN r0_rd_out[234]
    DIRECTION OUTPUT ;
    USE SIGNAL ;
    SHAPE ABUTMENT ;
    PORT
      LAYER met2 ;
      RECT 782.850 812.860 782.990 813.280 ;
    END
  END r0_rd_out[234]
  PIN r0_rd_out[235]
    DIRECTION OUTPUT ;
    USE SIGNAL ;
    SHAPE ABUTMENT ;
    PORT
      LAYER met2 ;
      RECT 790.210 812.860 790.350 813.280 ;
    END
  END r0_rd_out[235]
  PIN r0_rd_out[236]
    DIRECTION OUTPUT ;
    USE SIGNAL ;
    SHAPE ABUTMENT ;
    PORT
      LAYER met2 ;
      RECT 797.570 812.860 797.710 813.280 ;
    END
  END r0_rd_out[236]
  PIN r0_rd_out[237]
    DIRECTION OUTPUT ;
    USE SIGNAL ;
    SHAPE ABUTMENT ;
    PORT
      LAYER met2 ;
      RECT 804.930 812.860 805.070 813.280 ;
    END
  END r0_rd_out[237]
  PIN r0_rd_out[238]
    DIRECTION OUTPUT ;
    USE SIGNAL ;
    SHAPE ABUTMENT ;
    PORT
      LAYER met2 ;
      RECT 812.290 812.860 812.430 813.280 ;
    END
  END r0_rd_out[238]
  PIN r0_rd_out[239]
    DIRECTION OUTPUT ;
    USE SIGNAL ;
    SHAPE ABUTMENT ;
    PORT
      LAYER met2 ;
      RECT 819.650 812.860 819.790 813.280 ;
    END
  END r0_rd_out[239]
  PIN r0_rd_out[240]
    DIRECTION OUTPUT ;
    USE SIGNAL ;
    SHAPE ABUTMENT ;
    PORT
      LAYER met2 ;
      RECT 827.010 812.860 827.150 813.280 ;
    END
  END r0_rd_out[240]
  PIN r0_rd_out[241]
    DIRECTION OUTPUT ;
    USE SIGNAL ;
    SHAPE ABUTMENT ;
    PORT
      LAYER met2 ;
      RECT 834.370 812.860 834.510 813.280 ;
    END
  END r0_rd_out[241]
  PIN r0_rd_out[242]
    DIRECTION OUTPUT ;
    USE SIGNAL ;
    SHAPE ABUTMENT ;
    PORT
      LAYER met2 ;
      RECT 841.730 812.860 841.870 813.280 ;
    END
  END r0_rd_out[242]
  PIN r0_rd_out[243]
    DIRECTION OUTPUT ;
    USE SIGNAL ;
    SHAPE ABUTMENT ;
    PORT
      LAYER met2 ;
      RECT 849.090 812.860 849.230 813.280 ;
    END
  END r0_rd_out[243]
  PIN r0_rd_out[244]
    DIRECTION OUTPUT ;
    USE SIGNAL ;
    SHAPE ABUTMENT ;
    PORT
      LAYER met2 ;
      RECT 856.450 812.860 856.590 813.280 ;
    END
  END r0_rd_out[244]
  PIN r0_rd_out[245]
    DIRECTION OUTPUT ;
    USE SIGNAL ;
    SHAPE ABUTMENT ;
    PORT
      LAYER met2 ;
      RECT 863.810 812.860 863.950 813.280 ;
    END
  END r0_rd_out[245]
  PIN r0_rd_out[246]
    DIRECTION OUTPUT ;
    USE SIGNAL ;
    SHAPE ABUTMENT ;
    PORT
      LAYER met2 ;
      RECT 871.170 812.860 871.310 813.280 ;
    END
  END r0_rd_out[246]
  PIN r0_rd_out[247]
    DIRECTION OUTPUT ;
    USE SIGNAL ;
    SHAPE ABUTMENT ;
    PORT
      LAYER met2 ;
      RECT 878.530 812.860 878.670 813.280 ;
    END
  END r0_rd_out[247]
  PIN r0_rd_out[248]
    DIRECTION OUTPUT ;
    USE SIGNAL ;
    SHAPE ABUTMENT ;
    PORT
      LAYER met2 ;
      RECT 885.890 812.860 886.030 813.280 ;
    END
  END r0_rd_out[248]
  PIN r0_rd_out[249]
    DIRECTION OUTPUT ;
    USE SIGNAL ;
    SHAPE ABUTMENT ;
    PORT
      LAYER met2 ;
      RECT 893.250 812.860 893.390 813.280 ;
    END
  END r0_rd_out[249]
  PIN r0_rd_out[250]
    DIRECTION OUTPUT ;
    USE SIGNAL ;
    SHAPE ABUTMENT ;
    PORT
      LAYER met2 ;
      RECT 900.610 812.860 900.750 813.280 ;
    END
  END r0_rd_out[250]
  PIN r0_rd_out[251]
    DIRECTION OUTPUT ;
    USE SIGNAL ;
    SHAPE ABUTMENT ;
    PORT
      LAYER met2 ;
      RECT 907.970 812.860 908.110 813.280 ;
    END
  END r0_rd_out[251]
  PIN r0_rd_out[252]
    DIRECTION OUTPUT ;
    USE SIGNAL ;
    SHAPE ABUTMENT ;
    PORT
      LAYER met2 ;
      RECT 915.330 812.860 915.470 813.280 ;
    END
  END r0_rd_out[252]
  PIN r0_rd_out[253]
    DIRECTION OUTPUT ;
    USE SIGNAL ;
    SHAPE ABUTMENT ;
    PORT
      LAYER met2 ;
      RECT 922.690 812.860 922.830 813.280 ;
    END
  END r0_rd_out[253]
  PIN r0_rd_out[254]
    DIRECTION OUTPUT ;
    USE SIGNAL ;
    SHAPE ABUTMENT ;
    PORT
      LAYER met2 ;
      RECT 930.050 812.860 930.190 813.280 ;
    END
  END r0_rd_out[254]
  PIN r0_rd_out[255]
    DIRECTION OUTPUT ;
    USE SIGNAL ;
    SHAPE ABUTMENT ;
    PORT
      LAYER met2 ;
      RECT 937.410 812.860 937.550 813.280 ;
    END
  END r0_rd_out[255]
  PIN w0_addr_in[0]
    DIRECTION INPUT ;
    USE SIGNAL ;
    SHAPE ABUTMENT ;
    PORT
      LAYER met3 ;
      RECT 0.000 700.250 0.900 700.550 ;
    END
  END w0_addr_in[0]
  PIN w0_addr_in[1]
    DIRECTION INPUT ;
    USE SIGNAL ;
    SHAPE ABUTMENT ;
    PORT
      LAYER met3 ;
      RECT 0.000 711.130 0.900 711.430 ;
    END
  END w0_addr_in[1]
  PIN w0_addr_in[2]
    DIRECTION INPUT ;
    USE SIGNAL ;
    SHAPE ABUTMENT ;
    PORT
      LAYER met3 ;
      RECT 0.000 722.010 0.900 722.310 ;
    END
  END w0_addr_in[2]
  PIN w0_addr_in[3]
    DIRECTION INPUT ;
    USE SIGNAL ;
    SHAPE ABUTMENT ;
    PORT
      LAYER met3 ;
      RECT 0.000 732.890 0.900 733.190 ;
    END
  END w0_addr_in[3]
  PIN w0_addr_in[4]
    DIRECTION INPUT ;
    USE SIGNAL ;
    SHAPE ABUTMENT ;
    PORT
      LAYER met3 ;
      RECT 992.700 700.250 993.600 700.550 ;
    END
  END w0_addr_in[4]
  PIN w0_addr_in[5]
    DIRECTION INPUT ;
    USE SIGNAL ;
    SHAPE ABUTMENT ;
    PORT
      LAYER met3 ;
      RECT 992.700 711.130 993.600 711.430 ;
    END
  END w0_addr_in[5]
  PIN w0_addr_in[6]
    DIRECTION INPUT ;
    USE SIGNAL ;
    SHAPE ABUTMENT ;
    PORT
      LAYER met3 ;
      RECT 992.700 722.010 993.600 722.310 ;
    END
  END w0_addr_in[6]
  PIN w0_addr_in[7]
    DIRECTION INPUT ;
    USE SIGNAL ;
    SHAPE ABUTMENT ;
    PORT
      LAYER met3 ;
      RECT 992.700 732.890 993.600 733.190 ;
    END
  END w0_addr_in[7]
  PIN r0_addr_in[0]
    DIRECTION INPUT ;
    USE SIGNAL ;
    SHAPE ABUTMENT ;
    PORT
      LAYER met3 ;
      RECT 0.000 743.770 0.900 744.070 ;
    END
  END r0_addr_in[0]
  PIN r0_addr_in[1]
    DIRECTION INPUT ;
    USE SIGNAL ;
    SHAPE ABUTMENT ;
    PORT
      LAYER met3 ;
      RECT 0.000 754.650 0.900 754.950 ;
    END
  END r0_addr_in[1]
  PIN r0_addr_in[2]
    DIRECTION INPUT ;
    USE SIGNAL ;
    SHAPE ABUTMENT ;
    PORT
      LAYER met3 ;
      RECT 0.000 765.530 0.900 765.830 ;
    END
  END r0_addr_in[2]
  PIN r0_addr_in[3]
    DIRECTION INPUT ;
    USE SIGNAL ;
    SHAPE ABUTMENT ;
    PORT
      LAYER met3 ;
      RECT 0.000 776.410 0.900 776.710 ;
    END
  END r0_addr_in[3]
  PIN r0_addr_in[4]
    DIRECTION INPUT ;
    USE SIGNAL ;
    SHAPE ABUTMENT ;
    PORT
      LAYER met3 ;
      RECT 992.700 743.770 993.600 744.070 ;
    END
  END r0_addr_in[4]
  PIN r0_addr_in[5]
    DIRECTION INPUT ;
    USE SIGNAL ;
    SHAPE ABUTMENT ;
    PORT
      LAYER met3 ;
      RECT 992.700 754.650 993.600 754.950 ;
    END
  END r0_addr_in[5]
  PIN r0_addr_in[6]
    DIRECTION INPUT ;
    USE SIGNAL ;
    SHAPE ABUTMENT ;
    PORT
      LAYER met3 ;
      RECT 992.700 765.530 993.600 765.830 ;
    END
  END r0_addr_in[6]
  PIN r0_addr_in[7]
    DIRECTION INPUT ;
    USE SIGNAL ;
    SHAPE ABUTMENT ;
    PORT
      LAYER met3 ;
      RECT 992.700 776.410 993.600 776.710 ;
    END
  END r0_addr_in[7]
  PIN w0_we_in
    DIRECTION INPUT ;
    USE SIGNAL ;
    SHAPE ABUTMENT ;
    PORT
      LAYER met2 ;
      RECT 944.770 812.860 944.910 813.280 ;
    END
  END w0_we_in
  PIN w0_ce_in
    DIRECTION INPUT ;
    USE SIGNAL ;
    SHAPE ABUTMENT ;
    PORT
      LAYER met2 ;
      RECT 952.130 812.860 952.270 813.280 ;
    END
  END w0_ce_in
  PIN w0_clk
    DIRECTION INPUT ;
    USE SIGNAL ;
    SHAPE ABUTMENT ;
    PORT
      LAYER met2 ;
      RECT 959.490 812.860 959.630 813.280 ;
    END
  END w0_clk
  PIN r0_ce_in
    DIRECTION INPUT ;
    USE SIGNAL ;
    SHAPE ABUTMENT ;
    PORT
      LAYER met2 ;
      RECT 966.850 812.860 966.990 813.280 ;
    END
  END r0_ce_in
  PIN r0_clk
    DIRECTION INPUT ;
    USE SIGNAL ;
    SHAPE ABUTMENT ;
    PORT
      LAYER met2 ;
      RECT 974.210 812.860 974.350 813.280 ;
    END
  END r0_clk
  PIN VSS
    DIRECTION INOUT ;
    USE GROUND ;
    PORT
      LAYER met4 ;
      RECT 2.160 4.080 3.360 809.200 ;
      RECT 13.040 4.080 14.240 809.200 ;
      RECT 23.920 4.080 25.120 809.200 ;
      RECT 34.800 4.080 36.000 809.200 ;
      RECT 45.680 4.080 46.880 809.200 ;
      RECT 56.560 4.080 57.760 809.200 ;
      RECT 67.440 4.080 68.640 809.200 ;
      RECT 78.320 4.080 79.520 809.200 ;
      RECT 89.200 4.080 90.400 809.200 ;
      RECT 100.080 4.080 101.280 809.200 ;
      RECT 110.960 4.080 112.160 809.200 ;
      RECT 121.840 4.080 123.040 809.200 ;
      RECT 132.720 4.080 133.920 809.200 ;
      RECT 143.600 4.080 144.800 809.200 ;
      RECT 154.480 4.080 155.680 809.200 ;
      RECT 165.360 4.080 166.560 809.200 ;
      RECT 176.240 4.080 177.440 809.200 ;
      RECT 187.120 4.080 188.320 809.200 ;
      RECT 198.000 4.080 199.200 809.200 ;
      RECT 208.880 4.080 210.080 809.200 ;
      RECT 219.760 4.080 220.960 809.200 ;
      RECT 230.640 4.080 231.840 809.200 ;
      RECT 241.520 4.080 242.720 809.200 ;
      RECT 252.400 4.080 253.600 809.200 ;
      RECT 263.280 4.080 264.480 809.200 ;
      RECT 274.160 4.080 275.360 809.200 ;
      RECT 285.040 4.080 286.240 809.200 ;
      RECT 295.920 4.080 297.120 809.200 ;
      RECT 306.800 4.080 308.000 809.200 ;
      RECT 317.680 4.080 318.880 809.200 ;
      RECT 328.560 4.080 329.760 809.200 ;
      RECT 339.440 4.080 340.640 809.200 ;
      RECT 350.320 4.080 351.520 809.200 ;
      RECT 361.200 4.080 362.400 809.200 ;
      RECT 372.080 4.080 373.280 809.200 ;
      RECT 382.960 4.080 384.160 809.200 ;
      RECT 393.840 4.080 395.040 809.200 ;
      RECT 404.720 4.080 405.920 809.200 ;
      RECT 415.600 4.080 416.800 809.200 ;
      RECT 426.480 4.080 427.680 809.200 ;
      RECT 437.360 4.080 438.560 809.200 ;
      RECT 448.240 4.080 449.440 809.200 ;
      RECT 459.120 4.080 460.320 809.200 ;
      RECT 470.000 4.080 471.200 809.200 ;
      RECT 480.880 4.080 482.080 809.200 ;
      RECT 491.760 4.080 492.960 809.200 ;
      RECT 502.640 4.080 503.840 809.200 ;
      RECT 513.520 4.080 514.720 809.200 ;
      RECT 524.400 4.080 525.600 809.200 ;
      RECT 535.280 4.080 536.480 809.200 ;
      RECT 546.160 4.080 547.360 809.200 ;
      RECT 557.040 4.080 558.240 809.200 ;
      RECT 567.920 4.080 569.120 809.200 ;
      RECT 578.800 4.080 580.000 809.200 ;
      RECT 589.680 4.080 590.880 809.200 ;
      RECT 600.560 4.080 601.760 809.200 ;
      RECT 611.440 4.080 612.640 809.200 ;
      RECT 622.320 4.080 623.520 809.200 ;
      RECT 633.200 4.080 634.400 809.200 ;
      RECT 644.080 4.080 645.280 809.200 ;
      RECT 654.960 4.080 656.160 809.200 ;
      RECT 665.840 4.080 667.040 809.200 ;
      RECT 676.720 4.080 677.920 809.200 ;
      RECT 687.600 4.080 688.800 809.200 ;
      RECT 698.480 4.080 699.680 809.200 ;
      RECT 709.360 4.080 710.560 809.200 ;
      RECT 720.240 4.080 721.440 809.200 ;
      RECT 731.120 4.080 732.320 809.200 ;
      RECT 742.000 4.080 743.200 809.200 ;
      RECT 752.880 4.080 754.080 809.200 ;
      RECT 763.760 4.080 764.960 809.200 ;
      RECT 774.640 4.080 775.840 809.200 ;
      RECT 785.520 4.080 786.720 809.200 ;
      RECT 796.400 4.080 797.600 809.200 ;
      RECT 807.280 4.080 808.480 809.200 ;
      RECT 818.160 4.080 819.360 809.200 ;
      RECT 829.040 4.080 830.240 809.200 ;
      RECT 839.920 4.080 841.120 809.200 ;
      RECT 850.800 4.080 852.000 809.200 ;
      RECT 861.680 4.080 862.880 809.200 ;
      RECT 872.560 4.080 873.760 809.200 ;
      RECT 883.440 4.080 884.640 809.200 ;
      RECT 894.320 4.080 895.520 809.200 ;
      RECT 905.200 4.080 906.400 809.200 ;
      RECT 916.080 4.080 917.280 809.200 ;
      RECT 926.960 4.080 928.160 809.200 ;
      RECT 937.840 4.080 939.040 809.200 ;
      RECT 948.720 4.080 949.920 809.200 ;
      RECT 959.600 4.080 960.800 809.200 ;
      RECT 970.480 4.080 971.680 809.200 ;
      RECT 981.360 4.080 982.560 809.200 ;
      RECT 992.240 4.080 993.440 809.200 ;
    END
  END VSS
  PIN VDD
    DIRECTION INOUT ;
    USE POWER ;
    PORT
      LAYER met4 ;
      RECT 2.160 4.080 3.360 809.200 ;
      RECT 13.040 4.080 14.240 809.200 ;
      RECT 23.920 4.080 25.120 809.200 ;
      RECT 34.800 4.080 36.000 809.200 ;
      RECT 45.680 4.080 46.880 809.200 ;
      RECT 56.560 4.080 57.760 809.200 ;
      RECT 67.440 4.080 68.640 809.200 ;
      RECT 78.320 4.080 79.520 809.200 ;
      RECT 89.200 4.080 90.400 809.200 ;
      RECT 100.080 4.080 101.280 809.200 ;
      RECT 110.960 4.080 112.160 809.200 ;
      RECT 121.840 4.080 123.040 809.200 ;
      RECT 132.720 4.080 133.920 809.200 ;
      RECT 143.600 4.080 144.800 809.200 ;
      RECT 154.480 4.080 155.680 809.200 ;
      RECT 165.360 4.080 166.560 809.200 ;
      RECT 176.240 4.080 177.440 809.200 ;
      RECT 187.120 4.080 188.320 809.200 ;
      RECT 198.000 4.080 199.200 809.200 ;
      RECT 208.880 4.080 210.080 809.200 ;
      RECT 219.760 4.080 220.960 809.200 ;
      RECT 230.640 4.080 231.840 809.200 ;
      RECT 241.520 4.080 242.720 809.200 ;
      RECT 252.400 4.080 253.600 809.200 ;
      RECT 263.280 4.080 264.480 809.200 ;
      RECT 274.160 4.080 275.360 809.200 ;
      RECT 285.040 4.080 286.240 809.200 ;
      RECT 295.920 4.080 297.120 809.200 ;
      RECT 306.800 4.080 308.000 809.200 ;
      RECT 317.680 4.080 318.880 809.200 ;
      RECT 328.560 4.080 329.760 809.200 ;
      RECT 339.440 4.080 340.640 809.200 ;
      RECT 350.320 4.080 351.520 809.200 ;
      RECT 361.200 4.080 362.400 809.200 ;
      RECT 372.080 4.080 373.280 809.200 ;
      RECT 382.960 4.080 384.160 809.200 ;
      RECT 393.840 4.080 395.040 809.200 ;
      RECT 404.720 4.080 405.920 809.200 ;
      RECT 415.600 4.080 416.800 809.200 ;
      RECT 426.480 4.080 427.680 809.200 ;
      RECT 437.360 4.080 438.560 809.200 ;
      RECT 448.240 4.080 449.440 809.200 ;
      RECT 459.120 4.080 460.320 809.200 ;
      RECT 470.000 4.080 471.200 809.200 ;
      RECT 480.880 4.080 482.080 809.200 ;
      RECT 491.760 4.080 492.960 809.200 ;
      RECT 502.640 4.080 503.840 809.200 ;
      RECT 513.520 4.080 514.720 809.200 ;
      RECT 524.400 4.080 525.600 809.200 ;
      RECT 535.280 4.080 536.480 809.200 ;
      RECT 546.160 4.080 547.360 809.200 ;
      RECT 557.040 4.080 558.240 809.200 ;
      RECT 567.920 4.080 569.120 809.200 ;
      RECT 578.800 4.080 580.000 809.200 ;
      RECT 589.680 4.080 590.880 809.200 ;
      RECT 600.560 4.080 601.760 809.200 ;
      RECT 611.440 4.080 612.640 809.200 ;
      RECT 622.320 4.080 623.520 809.200 ;
      RECT 633.200 4.080 634.400 809.200 ;
      RECT 644.080 4.080 645.280 809.200 ;
      RECT 654.960 4.080 656.160 809.200 ;
      RECT 665.840 4.080 667.040 809.200 ;
      RECT 676.720 4.080 677.920 809.200 ;
      RECT 687.600 4.080 688.800 809.200 ;
      RECT 698.480 4.080 699.680 809.200 ;
      RECT 709.360 4.080 710.560 809.200 ;
      RECT 720.240 4.080 721.440 809.200 ;
      RECT 731.120 4.080 732.320 809.200 ;
      RECT 742.000 4.080 743.200 809.200 ;
      RECT 752.880 4.080 754.080 809.200 ;
      RECT 763.760 4.080 764.960 809.200 ;
      RECT 774.640 4.080 775.840 809.200 ;
      RECT 785.520 4.080 786.720 809.200 ;
      RECT 796.400 4.080 797.600 809.200 ;
      RECT 807.280 4.080 808.480 809.200 ;
      RECT 818.160 4.080 819.360 809.200 ;
      RECT 829.040 4.080 830.240 809.200 ;
      RECT 839.920 4.080 841.120 809.200 ;
      RECT 850.800 4.080 852.000 809.200 ;
      RECT 861.680 4.080 862.880 809.200 ;
      RECT 872.560 4.080 873.760 809.200 ;
      RECT 883.440 4.080 884.640 809.200 ;
      RECT 894.320 4.080 895.520 809.200 ;
      RECT 905.200 4.080 906.400 809.200 ;
      RECT 916.080 4.080 917.280 809.200 ;
      RECT 926.960 4.080 928.160 809.200 ;
      RECT 937.840 4.080 939.040 809.200 ;
      RECT 948.720 4.080 949.920 809.200 ;
      RECT 959.600 4.080 960.800 809.200 ;
      RECT 970.480 4.080 971.680 809.200 ;
      RECT 981.360 4.080 982.560 809.200 ;
      RECT 992.240 4.080 993.440 809.200 ;
    END
  END VDD
  OBS
    LAYER met1 ;
    RECT 0 0 993.600 813.280 ;
    LAYER met2 ;
    RECT 0 0 993.600 813.280 ;
    LAYER met3 ;
    RECT 0 0 993.600 813.280 ;
    LAYER met4 ;
    RECT 0 0 993.600 813.280 ;
  END
END fakeram_256x256_1r1w

END LIBRARY
